VERSION 5.8 ;
BUSBITCHARS "[]" ;
DIVIDERCHAR "/" ;
UNITS
    DATABASE MICRONS 1000 ;
END UNITS

VIA ino_fetch_via1_2_1000_440_1_2_410_410
  VIARULE via1Array ;
  CUTSIZE 0.19 0.19 ;
  LAYERS Metal1 Via1 Metal2 ;
  CUTSPACING 0.22 0.22 ;
  ENCLOSURE 0.05 0.125 0.005 0.05 ;
  ROWCOL 1 2 ;
END ino_fetch_via1_2_1000_440_1_2_410_410

VIA ino_fetch_via2_3_1000_440_1_2_410_410
  VIARULE via2Array ;
  CUTSIZE 0.19 0.19 ;
  LAYERS Metal2 Via2 Metal3 ;
  CUTSPACING 0.22 0.22 ;
  ENCLOSURE 0.005 0.05 0.05 0.005 ;
  ROWCOL 1 2 ;
END ino_fetch_via2_3_1000_440_1_2_410_410

VIA ino_fetch_via3_4_1000_440_1_2_410_410
  VIARULE via3Array ;
  CUTSIZE 0.19 0.19 ;
  LAYERS Metal3 Via3 Metal4 ;
  CUTSPACING 0.22 0.22 ;
  ENCLOSURE 0.05 0.005 0.2 0.05 ;
  ROWCOL 1 2 ;
END ino_fetch_via3_4_1000_440_1_2_410_410

VIA ino_fetch_via1_2_1000_350_1_2_410_410
  VIARULE via1Array ;
  CUTSIZE 0.19 0.19 ;
  LAYERS Metal1 Via1 Metal2 ;
  CUTSPACING 0.22 0.22 ;
  ENCLOSURE 0.05 0.08 0.005 0.05 ;
  ROWCOL 1 2 ;
END ino_fetch_via1_2_1000_350_1_2_410_410

VIA ino_fetch_via2_3_1000_530_1_2_410_410
  VIARULE via2Array ;
  CUTSIZE 0.19 0.19 ;
  LAYERS Metal2 Via2 Metal3 ;
  CUTSPACING 0.22 0.22 ;
  ENCLOSURE 0.005 0.05 0.05 0.005 ;
  ROWCOL 1 2 ;
END ino_fetch_via2_3_1000_530_1_2_410_410

VIA ino_fetch_via3_4_1000_350_1_2_410_410
  VIARULE via3Array ;
  CUTSIZE 0.19 0.19 ;
  LAYERS Metal3 Via3 Metal4 ;
  CUTSPACING 0.22 0.22 ;
  ENCLOSURE 0.05 0.005 0.2 0.05 ;
  ROWCOL 1 2 ;
END ino_fetch_via3_4_1000_350_1_2_410_410

VIA ino_fetch_via4_5_1000_2000_1_1_840_840
  VIARULE viaTop1Array ;
  CUTSIZE 0.42 0.42 ;
  LAYERS Metal4 TopVia1 TopMetal1 ;
  CUTSPACING 0.42 0.42 ;
  ENCLOSURE 0.29 0.1 0.42 0.79 ;
END ino_fetch_via4_5_1000_2000_1_1_840_840

VIA ino_fetch_via4_5_1000_1640_1_1_840_840
  VIARULE viaTop1Array ;
  CUTSIZE 0.42 0.42 ;
  LAYERS Metal4 TopVia1 TopMetal1 ;
  CUTSPACING 0.42 0.42 ;
  ENCLOSURE 0.29 0.1 0.42 0.61 ;
END ino_fetch_via4_5_1000_1640_1_1_840_840

VIA ino_fetch_via4_5_4420_2000_1_4_840_840
  VIARULE viaTop1Array ;
  CUTSIZE 0.42 0.42 ;
  LAYERS Metal4 TopVia1 TopMetal1 ;
  CUTSPACING 0.42 0.42 ;
  ENCLOSURE 0.74 0.79 0.42 0.79 ;
  ROWCOL 1 4 ;
END ino_fetch_via4_5_4420_2000_1_4_840_840

VIA ino_fetch_via4_5_2810_2000_1_2_840_840
  VIARULE viaTop1Array ;
  CUTSIZE 0.42 0.42 ;
  LAYERS Metal4 TopVia1 TopMetal1 ;
  CUTSPACING 0.42 0.42 ;
  ENCLOSURE 0.775 0.79 0.42 0.79 ;
  ROWCOL 1 2 ;
END ino_fetch_via4_5_2810_2000_1_2_840_840

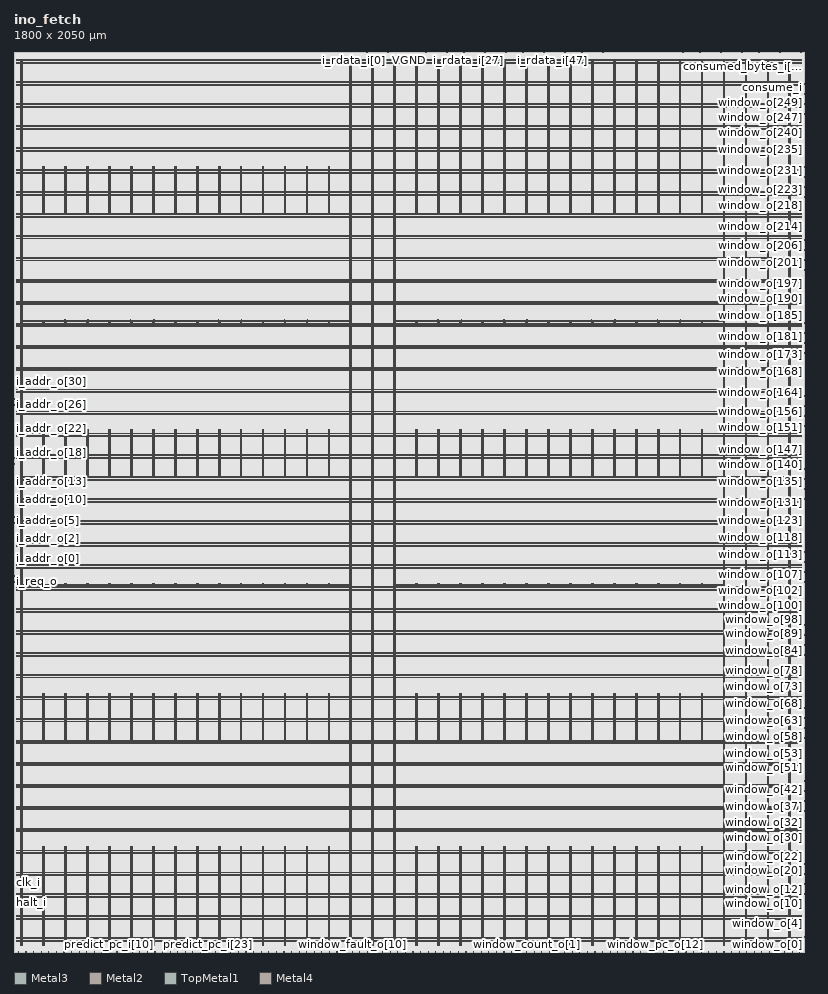
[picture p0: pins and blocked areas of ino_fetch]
MACRO ino_fetch
  FOREIGN ino_fetch 0 0 ;
  CLASS BLOCK ;
  SIZE 1800 BY 2050 ;
  PIN clk_i
    DIRECTION INPUT ;
    USE SIGNAL ;
    PORT
      LAYER Metal3 ;
        RECT  0 157.3 0.4 157.7 ;
    END
  END clk_i
  PIN consume_i
    DIRECTION INPUT ;
    USE SIGNAL ;
    PORT
      LAYER Metal3 ;
        RECT  1799.6 1969.18 1800 1969.58 ;
    END
  END consume_i
  PIN consumed_bytes_i[0]
    DIRECTION INPUT ;
    USE SIGNAL ;
    PORT
      LAYER Metal3 ;
        RECT  1799.6 1976.74 1800 1977.14 ;
    END
  END consumed_bytes_i[0]
  PIN consumed_bytes_i[1]
    DIRECTION INPUT ;
    USE SIGNAL ;
    PORT
      LAYER Metal3 ;
        RECT  1799.6 1984.3 1800 1984.7 ;
    END
  END consumed_bytes_i[1]
  PIN consumed_bytes_i[2]
    DIRECTION INPUT ;
    USE SIGNAL ;
    PORT
      LAYER Metal3 ;
        RECT  1799.6 1991.86 1800 1992.26 ;
    END
  END consumed_bytes_i[2]
  PIN consumed_bytes_i[3]
    DIRECTION INPUT ;
    USE SIGNAL ;
    PORT
      LAYER Metal3 ;
        RECT  1799.6 1999.42 1800 1999.82 ;
    END
  END consumed_bytes_i[3]
  PIN consumed_bytes_i[4]
    DIRECTION INPUT ;
    USE SIGNAL ;
    PORT
      LAYER Metal3 ;
        RECT  1799.6 2006.98 1800 2007.38 ;
    END
  END consumed_bytes_i[4]
  PIN consumed_bytes_i[5]
    DIRECTION INPUT ;
    USE SIGNAL ;
    PORT
      LAYER Metal3 ;
        RECT  1799.6 2014.54 1800 2014.94 ;
    END
  END consumed_bytes_i[5]
  PIN decode_stop_i
    DIRECTION INPUT ;
    USE SIGNAL ;
    PORT
      LAYER Metal2 ;
        RECT  9.88 0 10.28 0.4 ;
    END
  END decode_stop_i
  PIN halt_i
    DIRECTION INPUT ;
    USE SIGNAL ;
    PORT
      LAYER Metal3 ;
        RECT  0 130.42 0.4 130.82 ;
    END
  END halt_i
  PIN i_addr_o[0]
    DIRECTION OUTPUT ;
    USE SIGNAL ;
    PORT
      LAYER Metal3 ;
        RECT  0 896.5 0.4 896.9 ;
    END
  END i_addr_o[0]
  PIN i_addr_o[10]
    DIRECTION OUTPUT ;
    USE SIGNAL ;
    PORT
      LAYER Metal3 ;
        RECT  0 1030.9 0.4 1031.3 ;
    END
  END i_addr_o[10]
  PIN i_addr_o[11]
    DIRECTION OUTPUT ;
    USE SIGNAL ;
    PORT
      LAYER Metal3 ;
        RECT  0 1044.34 0.4 1044.74 ;
    END
  END i_addr_o[11]
  PIN i_addr_o[12]
    DIRECTION OUTPUT ;
    USE SIGNAL ;
    PORT
      LAYER Metal3 ;
        RECT  0 1057.78 0.4 1058.18 ;
    END
  END i_addr_o[12]
  PIN i_addr_o[13]
    DIRECTION OUTPUT ;
    USE SIGNAL ;
    PORT
      LAYER Metal3 ;
        RECT  0 1071.22 0.4 1071.62 ;
    END
  END i_addr_o[13]
  PIN i_addr_o[14]
    DIRECTION OUTPUT ;
    USE SIGNAL ;
    PORT
      LAYER Metal3 ;
        RECT  0 1084.66 0.4 1085.06 ;
    END
  END i_addr_o[14]
  PIN i_addr_o[15]
    DIRECTION OUTPUT ;
    USE SIGNAL ;
    PORT
      LAYER Metal3 ;
        RECT  0 1098.1 0.4 1098.5 ;
    END
  END i_addr_o[15]
  PIN i_addr_o[16]
    DIRECTION OUTPUT ;
    USE SIGNAL ;
    PORT
      LAYER Metal3 ;
        RECT  0 1111.54 0.4 1111.94 ;
    END
  END i_addr_o[16]
  PIN i_addr_o[17]
    DIRECTION OUTPUT ;
    USE SIGNAL ;
    PORT
      LAYER Metal3 ;
        RECT  0 1124.98 0.4 1125.38 ;
    END
  END i_addr_o[17]
  PIN i_addr_o[18]
    DIRECTION OUTPUT ;
    USE SIGNAL ;
    PORT
      LAYER Metal3 ;
        RECT  0 1138.42 0.4 1138.82 ;
    END
  END i_addr_o[18]
  PIN i_addr_o[19]
    DIRECTION OUTPUT ;
    USE SIGNAL ;
    PORT
      LAYER Metal3 ;
        RECT  0 1151.86 0.4 1152.26 ;
    END
  END i_addr_o[19]
  PIN i_addr_o[1]
    DIRECTION OUTPUT ;
    USE SIGNAL ;
    PORT
      LAYER Metal3 ;
        RECT  0 909.94 0.4 910.34 ;
    END
  END i_addr_o[1]
  PIN i_addr_o[20]
    DIRECTION OUTPUT ;
    USE SIGNAL ;
    PORT
      LAYER Metal3 ;
        RECT  0 1165.3 0.4 1165.7 ;
    END
  END i_addr_o[20]
  PIN i_addr_o[21]
    DIRECTION OUTPUT ;
    USE SIGNAL ;
    PORT
      LAYER Metal3 ;
        RECT  0 1178.74 0.4 1179.14 ;
    END
  END i_addr_o[21]
  PIN i_addr_o[22]
    DIRECTION OUTPUT ;
    USE SIGNAL ;
    PORT
      LAYER Metal3 ;
        RECT  0 1192.18 0.4 1192.58 ;
    END
  END i_addr_o[22]
  PIN i_addr_o[23]
    DIRECTION OUTPUT ;
    USE SIGNAL ;
    PORT
      LAYER Metal3 ;
        RECT  0 1205.62 0.4 1206.02 ;
    END
  END i_addr_o[23]
  PIN i_addr_o[24]
    DIRECTION OUTPUT ;
    USE SIGNAL ;
    PORT
      LAYER Metal3 ;
        RECT  0 1219.06 0.4 1219.46 ;
    END
  END i_addr_o[24]
  PIN i_addr_o[25]
    DIRECTION OUTPUT ;
    USE SIGNAL ;
    PORT
      LAYER Metal3 ;
        RECT  0 1232.5 0.4 1232.9 ;
    END
  END i_addr_o[25]
  PIN i_addr_o[26]
    DIRECTION OUTPUT ;
    USE SIGNAL ;
    PORT
      LAYER Metal3 ;
        RECT  0 1245.94 0.4 1246.34 ;
    END
  END i_addr_o[26]
  PIN i_addr_o[27]
    DIRECTION OUTPUT ;
    USE SIGNAL ;
    PORT
      LAYER Metal3 ;
        RECT  0 1259.38 0.4 1259.78 ;
    END
  END i_addr_o[27]
  PIN i_addr_o[28]
    DIRECTION OUTPUT ;
    USE SIGNAL ;
    PORT
      LAYER Metal3 ;
        RECT  0 1272.82 0.4 1273.22 ;
    END
  END i_addr_o[28]
  PIN i_addr_o[29]
    DIRECTION OUTPUT ;
    USE SIGNAL ;
    PORT
      LAYER Metal3 ;
        RECT  0 1286.26 0.4 1286.66 ;
    END
  END i_addr_o[29]
  PIN i_addr_o[2]
    DIRECTION OUTPUT ;
    USE SIGNAL ;
    PORT
      LAYER Metal3 ;
        RECT  0 923.38 0.4 923.78 ;
    END
  END i_addr_o[2]
  PIN i_addr_o[30]
    DIRECTION OUTPUT ;
    USE SIGNAL ;
    PORT
      LAYER Metal3 ;
        RECT  0 1299.7 0.4 1300.1 ;
    END
  END i_addr_o[30]
  PIN i_addr_o[31]
    DIRECTION OUTPUT ;
    USE SIGNAL ;
    PORT
      LAYER Metal3 ;
        RECT  0 1313.14 0.4 1313.54 ;
    END
  END i_addr_o[31]
  PIN i_addr_o[3]
    DIRECTION OUTPUT ;
    USE SIGNAL ;
    PORT
      LAYER Metal3 ;
        RECT  0 936.82 0.4 937.22 ;
    END
  END i_addr_o[3]
  PIN i_addr_o[4]
    DIRECTION OUTPUT ;
    USE SIGNAL ;
    PORT
      LAYER Metal3 ;
        RECT  0 950.26 0.4 950.66 ;
    END
  END i_addr_o[4]
  PIN i_addr_o[5]
    DIRECTION OUTPUT ;
    USE SIGNAL ;
    PORT
      LAYER Metal3 ;
        RECT  0 963.7 0.4 964.1 ;
    END
  END i_addr_o[5]
  PIN i_addr_o[6]
    DIRECTION OUTPUT ;
    USE SIGNAL ;
    PORT
      LAYER Metal3 ;
        RECT  0 977.14 0.4 977.54 ;
    END
  END i_addr_o[6]
  PIN i_addr_o[7]
    DIRECTION OUTPUT ;
    USE SIGNAL ;
    PORT
      LAYER Metal3 ;
        RECT  0 990.58 0.4 990.98 ;
    END
  END i_addr_o[7]
  PIN i_addr_o[8]
    DIRECTION OUTPUT ;
    USE SIGNAL ;
    PORT
      LAYER Metal3 ;
        RECT  0 1004.02 0.4 1004.42 ;
    END
  END i_addr_o[8]
  PIN i_addr_o[9]
    DIRECTION OUTPUT ;
    USE SIGNAL ;
    PORT
      LAYER Metal3 ;
        RECT  0 1017.46 0.4 1017.86 ;
    END
  END i_addr_o[9]
  PIN i_fault_i
    DIRECTION INPUT ;
    USE SIGNAL ;
    PORT
      LAYER Metal3 ;
        RECT  0 883.06 0.4 883.46 ;
    END
  END i_fault_i
  PIN i_rdata_i[0]
    DIRECTION INPUT ;
    USE SIGNAL ;
    PORT
      LAYER Metal2 ;
        RECT  775 2049.6 775.4 2050 ;
    END
  END i_rdata_i[0]
  PIN i_rdata_i[10]
    DIRECTION INPUT ;
    USE SIGNAL ;
    PORT
      LAYER Metal2 ;
        RECT  871 2049.6 871.4 2050 ;
    END
  END i_rdata_i[10]
  PIN i_rdata_i[11]
    DIRECTION INPUT ;
    USE SIGNAL ;
    PORT
      LAYER Metal2 ;
        RECT  880.6 2049.6 881 2050 ;
    END
  END i_rdata_i[11]
  PIN i_rdata_i[12]
    DIRECTION INPUT ;
    USE SIGNAL ;
    PORT
      LAYER Metal2 ;
        RECT  890.2 2049.6 890.6 2050 ;
    END
  END i_rdata_i[12]
  PIN i_rdata_i[13]
    DIRECTION INPUT ;
    USE SIGNAL ;
    PORT
      LAYER Metal2 ;
        RECT  899.8 2049.6 900.2 2050 ;
    END
  END i_rdata_i[13]
  PIN i_rdata_i[14]
    DIRECTION INPUT ;
    USE SIGNAL ;
    PORT
      LAYER Metal2 ;
        RECT  909.4 2049.6 909.8 2050 ;
    END
  END i_rdata_i[14]
  PIN i_rdata_i[15]
    DIRECTION INPUT ;
    USE SIGNAL ;
    PORT
      LAYER Metal2 ;
        RECT  919 2049.6 919.4 2050 ;
    END
  END i_rdata_i[15]
  PIN i_rdata_i[16]
    DIRECTION INPUT ;
    USE SIGNAL ;
    PORT
      LAYER Metal2 ;
        RECT  928.6 2049.6 929 2050 ;
    END
  END i_rdata_i[16]
  PIN i_rdata_i[17]
    DIRECTION INPUT ;
    USE SIGNAL ;
    PORT
      LAYER Metal2 ;
        RECT  938.2 2049.6 938.6 2050 ;
    END
  END i_rdata_i[17]
  PIN i_rdata_i[18]
    DIRECTION INPUT ;
    USE SIGNAL ;
    PORT
      LAYER Metal2 ;
        RECT  947.8 2049.6 948.2 2050 ;
    END
  END i_rdata_i[18]
  PIN i_rdata_i[19]
    DIRECTION INPUT ;
    USE SIGNAL ;
    PORT
      LAYER Metal2 ;
        RECT  957.4 2049.6 957.8 2050 ;
    END
  END i_rdata_i[19]
  PIN i_rdata_i[1]
    DIRECTION INPUT ;
    USE SIGNAL ;
    PORT
      LAYER Metal2 ;
        RECT  784.6 2049.6 785 2050 ;
    END
  END i_rdata_i[1]
  PIN i_rdata_i[20]
    DIRECTION INPUT ;
    USE SIGNAL ;
    PORT
      LAYER Metal2 ;
        RECT  967 2049.6 967.4 2050 ;
    END
  END i_rdata_i[20]
  PIN i_rdata_i[21]
    DIRECTION INPUT ;
    USE SIGNAL ;
    PORT
      LAYER Metal2 ;
        RECT  976.6 2049.6 977 2050 ;
    END
  END i_rdata_i[21]
  PIN i_rdata_i[22]
    DIRECTION INPUT ;
    USE SIGNAL ;
    PORT
      LAYER Metal2 ;
        RECT  986.2 2049.6 986.6 2050 ;
    END
  END i_rdata_i[22]
  PIN i_rdata_i[23]
    DIRECTION INPUT ;
    USE SIGNAL ;
    PORT
      LAYER Metal2 ;
        RECT  995.8 2049.6 996.2 2050 ;
    END
  END i_rdata_i[23]
  PIN i_rdata_i[24]
    DIRECTION INPUT ;
    USE SIGNAL ;
    PORT
      LAYER Metal2 ;
        RECT  1005.4 2049.6 1005.8 2050 ;
    END
  END i_rdata_i[24]
  PIN i_rdata_i[25]
    DIRECTION INPUT ;
    USE SIGNAL ;
    PORT
      LAYER Metal2 ;
        RECT  1015 2049.6 1015.4 2050 ;
    END
  END i_rdata_i[25]
  PIN i_rdata_i[26]
    DIRECTION INPUT ;
    USE SIGNAL ;
    PORT
      LAYER Metal2 ;
        RECT  1024.6 2049.6 1025 2050 ;
    END
  END i_rdata_i[26]
  PIN i_rdata_i[27]
    DIRECTION INPUT ;
    USE SIGNAL ;
    PORT
      LAYER Metal2 ;
        RECT  1034.2 2049.6 1034.6 2050 ;
    END
  END i_rdata_i[27]
  PIN i_rdata_i[28]
    DIRECTION INPUT ;
    USE SIGNAL ;
    PORT
      LAYER Metal2 ;
        RECT  1043.8 2049.6 1044.2 2050 ;
    END
  END i_rdata_i[28]
  PIN i_rdata_i[29]
    DIRECTION INPUT ;
    USE SIGNAL ;
    PORT
      LAYER Metal2 ;
        RECT  1053.4 2049.6 1053.8 2050 ;
    END
  END i_rdata_i[29]
  PIN i_rdata_i[2]
    DIRECTION INPUT ;
    USE SIGNAL ;
    PORT
      LAYER Metal2 ;
        RECT  794.2 2049.6 794.6 2050 ;
    END
  END i_rdata_i[2]
  PIN i_rdata_i[30]
    DIRECTION INPUT ;
    USE SIGNAL ;
    PORT
      LAYER Metal2 ;
        RECT  1063 2049.6 1063.4 2050 ;
    END
  END i_rdata_i[30]
  PIN i_rdata_i[31]
    DIRECTION INPUT ;
    USE SIGNAL ;
    PORT
      LAYER Metal2 ;
        RECT  1072.6 2049.6 1073 2050 ;
    END
  END i_rdata_i[31]
  PIN i_rdata_i[32]
    DIRECTION INPUT ;
    USE SIGNAL ;
    PORT
      LAYER Metal2 ;
        RECT  1082.2 2049.6 1082.6 2050 ;
    END
  END i_rdata_i[32]
  PIN i_rdata_i[33]
    DIRECTION INPUT ;
    USE SIGNAL ;
    PORT
      LAYER Metal2 ;
        RECT  1091.8 2049.6 1092.2 2050 ;
    END
  END i_rdata_i[33]
  PIN i_rdata_i[34]
    DIRECTION INPUT ;
    USE SIGNAL ;
    PORT
      LAYER Metal2 ;
        RECT  1101.4 2049.6 1101.8 2050 ;
    END
  END i_rdata_i[34]
  PIN i_rdata_i[35]
    DIRECTION INPUT ;
    USE SIGNAL ;
    PORT
      LAYER Metal2 ;
        RECT  1111 2049.6 1111.4 2050 ;
    END
  END i_rdata_i[35]
  PIN i_rdata_i[36]
    DIRECTION INPUT ;
    USE SIGNAL ;
    PORT
      LAYER Metal2 ;
        RECT  1120.6 2049.6 1121 2050 ;
    END
  END i_rdata_i[36]
  PIN i_rdata_i[37]
    DIRECTION INPUT ;
    USE SIGNAL ;
    PORT
      LAYER Metal2 ;
        RECT  1130.2 2049.6 1130.6 2050 ;
    END
  END i_rdata_i[37]
  PIN i_rdata_i[38]
    DIRECTION INPUT ;
    USE SIGNAL ;
    PORT
      LAYER Metal2 ;
        RECT  1139.8 2049.6 1140.2 2050 ;
    END
  END i_rdata_i[38]
  PIN i_rdata_i[39]
    DIRECTION INPUT ;
    USE SIGNAL ;
    PORT
      LAYER Metal2 ;
        RECT  1149.4 2049.6 1149.8 2050 ;
    END
  END i_rdata_i[39]
  PIN i_rdata_i[3]
    DIRECTION INPUT ;
    USE SIGNAL ;
    PORT
      LAYER Metal2 ;
        RECT  803.8 2049.6 804.2 2050 ;
    END
  END i_rdata_i[3]
  PIN i_rdata_i[40]
    DIRECTION INPUT ;
    USE SIGNAL ;
    PORT
      LAYER Metal2 ;
        RECT  1159 2049.6 1159.4 2050 ;
    END
  END i_rdata_i[40]
  PIN i_rdata_i[41]
    DIRECTION INPUT ;
    USE SIGNAL ;
    PORT
      LAYER Metal2 ;
        RECT  1168.6 2049.6 1169 2050 ;
    END
  END i_rdata_i[41]
  PIN i_rdata_i[42]
    DIRECTION INPUT ;
    USE SIGNAL ;
    PORT
      LAYER Metal2 ;
        RECT  1178.2 2049.6 1178.6 2050 ;
    END
  END i_rdata_i[42]
  PIN i_rdata_i[43]
    DIRECTION INPUT ;
    USE SIGNAL ;
    PORT
      LAYER Metal2 ;
        RECT  1187.8 2049.6 1188.2 2050 ;
    END
  END i_rdata_i[43]
  PIN i_rdata_i[44]
    DIRECTION INPUT ;
    USE SIGNAL ;
    PORT
      LAYER Metal2 ;
        RECT  1197.4 2049.6 1197.8 2050 ;
    END
  END i_rdata_i[44]
  PIN i_rdata_i[45]
    DIRECTION INPUT ;
    USE SIGNAL ;
    PORT
      LAYER Metal2 ;
        RECT  1207 2049.6 1207.4 2050 ;
    END
  END i_rdata_i[45]
  PIN i_rdata_i[46]
    DIRECTION INPUT ;
    USE SIGNAL ;
    PORT
      LAYER Metal2 ;
        RECT  1216.6 2049.6 1217 2050 ;
    END
  END i_rdata_i[46]
  PIN i_rdata_i[47]
    DIRECTION INPUT ;
    USE SIGNAL ;
    PORT
      LAYER Metal2 ;
        RECT  1226.2 2049.6 1226.6 2050 ;
    END
  END i_rdata_i[47]
  PIN i_rdata_i[48]
    DIRECTION INPUT ;
    USE SIGNAL ;
    PORT
      LAYER Metal2 ;
        RECT  1235.8 2049.6 1236.2 2050 ;
    END
  END i_rdata_i[48]
  PIN i_rdata_i[49]
    DIRECTION INPUT ;
    USE SIGNAL ;
    PORT
      LAYER Metal2 ;
        RECT  1245.4 2049.6 1245.8 2050 ;
    END
  END i_rdata_i[49]
  PIN i_rdata_i[4]
    DIRECTION INPUT ;
    USE SIGNAL ;
    PORT
      LAYER Metal2 ;
        RECT  813.4 2049.6 813.8 2050 ;
    END
  END i_rdata_i[4]
  PIN i_rdata_i[50]
    DIRECTION INPUT ;
    USE SIGNAL ;
    PORT
      LAYER Metal2 ;
        RECT  1255 2049.6 1255.4 2050 ;
    END
  END i_rdata_i[50]
  PIN i_rdata_i[51]
    DIRECTION INPUT ;
    USE SIGNAL ;
    PORT
      LAYER Metal2 ;
        RECT  1264.6 2049.6 1265 2050 ;
    END
  END i_rdata_i[51]
  PIN i_rdata_i[52]
    DIRECTION INPUT ;
    USE SIGNAL ;
    PORT
      LAYER Metal2 ;
        RECT  1274.2 2049.6 1274.6 2050 ;
    END
  END i_rdata_i[52]
  PIN i_rdata_i[53]
    DIRECTION INPUT ;
    USE SIGNAL ;
    PORT
      LAYER Metal2 ;
        RECT  1283.8 2049.6 1284.2 2050 ;
    END
  END i_rdata_i[53]
  PIN i_rdata_i[54]
    DIRECTION INPUT ;
    USE SIGNAL ;
    PORT
      LAYER Metal2 ;
        RECT  1293.4 2049.6 1293.8 2050 ;
    END
  END i_rdata_i[54]
  PIN i_rdata_i[55]
    DIRECTION INPUT ;
    USE SIGNAL ;
    PORT
      LAYER Metal2 ;
        RECT  1303 2049.6 1303.4 2050 ;
    END
  END i_rdata_i[55]
  PIN i_rdata_i[56]
    DIRECTION INPUT ;
    USE SIGNAL ;
    PORT
      LAYER Metal2 ;
        RECT  1312.6 2049.6 1313 2050 ;
    END
  END i_rdata_i[56]
  PIN i_rdata_i[57]
    DIRECTION INPUT ;
    USE SIGNAL ;
    PORT
      LAYER Metal2 ;
        RECT  1322.2 2049.6 1322.6 2050 ;
    END
  END i_rdata_i[57]
  PIN i_rdata_i[58]
    DIRECTION INPUT ;
    USE SIGNAL ;
    PORT
      LAYER Metal2 ;
        RECT  1331.8 2049.6 1332.2 2050 ;
    END
  END i_rdata_i[58]
  PIN i_rdata_i[59]
    DIRECTION INPUT ;
    USE SIGNAL ;
    PORT
      LAYER Metal2 ;
        RECT  1341.4 2049.6 1341.8 2050 ;
    END
  END i_rdata_i[59]
  PIN i_rdata_i[5]
    DIRECTION INPUT ;
    USE SIGNAL ;
    PORT
      LAYER Metal2 ;
        RECT  823 2049.6 823.4 2050 ;
    END
  END i_rdata_i[5]
  PIN i_rdata_i[60]
    DIRECTION INPUT ;
    USE SIGNAL ;
    PORT
      LAYER Metal2 ;
        RECT  1351 2049.6 1351.4 2050 ;
    END
  END i_rdata_i[60]
  PIN i_rdata_i[61]
    DIRECTION INPUT ;
    USE SIGNAL ;
    PORT
      LAYER Metal2 ;
        RECT  1360.6 2049.6 1361 2050 ;
    END
  END i_rdata_i[61]
  PIN i_rdata_i[62]
    DIRECTION INPUT ;
    USE SIGNAL ;
    PORT
      LAYER Metal2 ;
        RECT  1370.2 2049.6 1370.6 2050 ;
    END
  END i_rdata_i[62]
  PIN i_rdata_i[63]
    DIRECTION INPUT ;
    USE SIGNAL ;
    PORT
      LAYER Metal2 ;
        RECT  1379.8 2049.6 1380.2 2050 ;
    END
  END i_rdata_i[63]
  PIN i_rdata_i[6]
    DIRECTION INPUT ;
    USE SIGNAL ;
    PORT
      LAYER Metal2 ;
        RECT  832.6 2049.6 833 2050 ;
    END
  END i_rdata_i[6]
  PIN i_rdata_i[7]
    DIRECTION INPUT ;
    USE SIGNAL ;
    PORT
      LAYER Metal2 ;
        RECT  842.2 2049.6 842.6 2050 ;
    END
  END i_rdata_i[7]
  PIN i_rdata_i[8]
    DIRECTION INPUT ;
    USE SIGNAL ;
    PORT
      LAYER Metal2 ;
        RECT  851.8 2049.6 852.2 2050 ;
    END
  END i_rdata_i[8]
  PIN i_rdata_i[9]
    DIRECTION INPUT ;
    USE SIGNAL ;
    PORT
      LAYER Metal2 ;
        RECT  861.4 2049.6 861.8 2050 ;
    END
  END i_rdata_i[9]
  PIN i_ready_i
    DIRECTION INPUT ;
    USE SIGNAL ;
    PORT
      LAYER Metal3 ;
        RECT  0 856.18 0.4 856.58 ;
    END
  END i_ready_i
  PIN i_req_o
    DIRECTION OUTPUT ;
    USE SIGNAL ;
    PORT
      LAYER Metal3 ;
        RECT  0 842.74 0.4 843.14 ;
    END
  END i_req_o
  PIN i_rvalid_i
    DIRECTION INPUT ;
    USE SIGNAL ;
    PORT
      LAYER Metal3 ;
        RECT  0 869.62 0.4 870.02 ;
    END
  END i_rvalid_i
  PIN predict_pc_i[0]
    DIRECTION INPUT ;
    USE SIGNAL ;
    PORT
      LAYER Metal2 ;
        RECT  44.44 0 44.84 0.4 ;
    END
  END predict_pc_i[0]
  PIN predict_pc_i[10]
    DIRECTION INPUT ;
    USE SIGNAL ;
    PORT
      LAYER Metal2 ;
        RECT  217.24 0 217.64 0.4 ;
    END
  END predict_pc_i[10]
  PIN predict_pc_i[11]
    DIRECTION INPUT ;
    USE SIGNAL ;
    PORT
      LAYER Metal2 ;
        RECT  234.52 0 234.92 0.4 ;
    END
  END predict_pc_i[11]
  PIN predict_pc_i[12]
    DIRECTION INPUT ;
    USE SIGNAL ;
    PORT
      LAYER Metal2 ;
        RECT  251.8 0 252.2 0.4 ;
    END
  END predict_pc_i[12]
  PIN predict_pc_i[13]
    DIRECTION INPUT ;
    USE SIGNAL ;
    PORT
      LAYER Metal2 ;
        RECT  269.08 0 269.48 0.4 ;
    END
  END predict_pc_i[13]
  PIN predict_pc_i[14]
    DIRECTION INPUT ;
    USE SIGNAL ;
    PORT
      LAYER Metal2 ;
        RECT  286.36 0 286.76 0.4 ;
    END
  END predict_pc_i[14]
  PIN predict_pc_i[15]
    DIRECTION INPUT ;
    USE SIGNAL ;
    PORT
      LAYER Metal2 ;
        RECT  303.64 0 304.04 0.4 ;
    END
  END predict_pc_i[15]
  PIN predict_pc_i[16]
    DIRECTION INPUT ;
    USE SIGNAL ;
    PORT
      LAYER Metal2 ;
        RECT  320.92 0 321.32 0.4 ;
    END
  END predict_pc_i[16]
  PIN predict_pc_i[17]
    DIRECTION INPUT ;
    USE SIGNAL ;
    PORT
      LAYER Metal2 ;
        RECT  338.2 0 338.6 0.4 ;
    END
  END predict_pc_i[17]
  PIN predict_pc_i[18]
    DIRECTION INPUT ;
    USE SIGNAL ;
    PORT
      LAYER Metal2 ;
        RECT  355.48 0 355.88 0.4 ;
    END
  END predict_pc_i[18]
  PIN predict_pc_i[19]
    DIRECTION INPUT ;
    USE SIGNAL ;
    PORT
      LAYER Metal2 ;
        RECT  372.76 0 373.16 0.4 ;
    END
  END predict_pc_i[19]
  PIN predict_pc_i[1]
    DIRECTION INPUT ;
    USE SIGNAL ;
    PORT
      LAYER Metal2 ;
        RECT  61.72 0 62.12 0.4 ;
    END
  END predict_pc_i[1]
  PIN predict_pc_i[20]
    DIRECTION INPUT ;
    USE SIGNAL ;
    PORT
      LAYER Metal2 ;
        RECT  390.04 0 390.44 0.4 ;
    END
  END predict_pc_i[20]
  PIN predict_pc_i[21]
    DIRECTION INPUT ;
    USE SIGNAL ;
    PORT
      LAYER Metal2 ;
        RECT  407.32 0 407.72 0.4 ;
    END
  END predict_pc_i[21]
  PIN predict_pc_i[22]
    DIRECTION INPUT ;
    USE SIGNAL ;
    PORT
      LAYER Metal2 ;
        RECT  424.6 0 425 0.4 ;
    END
  END predict_pc_i[22]
  PIN predict_pc_i[23]
    DIRECTION INPUT ;
    USE SIGNAL ;
    PORT
      LAYER Metal2 ;
        RECT  441.88 0 442.28 0.4 ;
    END
  END predict_pc_i[23]
  PIN predict_pc_i[24]
    DIRECTION INPUT ;
    USE SIGNAL ;
    PORT
      LAYER Metal2 ;
        RECT  459.16 0 459.56 0.4 ;
    END
  END predict_pc_i[24]
  PIN predict_pc_i[25]
    DIRECTION INPUT ;
    USE SIGNAL ;
    PORT
      LAYER Metal2 ;
        RECT  476.44 0 476.84 0.4 ;
    END
  END predict_pc_i[25]
  PIN predict_pc_i[26]
    DIRECTION INPUT ;
    USE SIGNAL ;
    PORT
      LAYER Metal2 ;
        RECT  493.72 0 494.12 0.4 ;
    END
  END predict_pc_i[26]
  PIN predict_pc_i[27]
    DIRECTION INPUT ;
    USE SIGNAL ;
    PORT
      LAYER Metal2 ;
        RECT  511 0 511.4 0.4 ;
    END
  END predict_pc_i[27]
  PIN predict_pc_i[28]
    DIRECTION INPUT ;
    USE SIGNAL ;
    PORT
      LAYER Metal2 ;
        RECT  528.28 0 528.68 0.4 ;
    END
  END predict_pc_i[28]
  PIN predict_pc_i[29]
    DIRECTION INPUT ;
    USE SIGNAL ;
    PORT
      LAYER Metal2 ;
        RECT  545.56 0 545.96 0.4 ;
    END
  END predict_pc_i[29]
  PIN predict_pc_i[2]
    DIRECTION INPUT ;
    USE SIGNAL ;
    PORT
      LAYER Metal2 ;
        RECT  79 0 79.4 0.4 ;
    END
  END predict_pc_i[2]
  PIN predict_pc_i[30]
    DIRECTION INPUT ;
    USE SIGNAL ;
    PORT
      LAYER Metal2 ;
        RECT  562.84 0 563.24 0.4 ;
    END
  END predict_pc_i[30]
  PIN predict_pc_i[31]
    DIRECTION INPUT ;
    USE SIGNAL ;
    PORT
      LAYER Metal2 ;
        RECT  580.12 0 580.52 0.4 ;
    END
  END predict_pc_i[31]
  PIN predict_pc_i[3]
    DIRECTION INPUT ;
    USE SIGNAL ;
    PORT
      LAYER Metal2 ;
        RECT  96.28 0 96.68 0.4 ;
    END
  END predict_pc_i[3]
  PIN predict_pc_i[4]
    DIRECTION INPUT ;
    USE SIGNAL ;
    PORT
      LAYER Metal2 ;
        RECT  113.56 0 113.96 0.4 ;
    END
  END predict_pc_i[4]
  PIN predict_pc_i[5]
    DIRECTION INPUT ;
    USE SIGNAL ;
    PORT
      LAYER Metal2 ;
        RECT  130.84 0 131.24 0.4 ;
    END
  END predict_pc_i[5]
  PIN predict_pc_i[6]
    DIRECTION INPUT ;
    USE SIGNAL ;
    PORT
      LAYER Metal2 ;
        RECT  148.12 0 148.52 0.4 ;
    END
  END predict_pc_i[6]
  PIN predict_pc_i[7]
    DIRECTION INPUT ;
    USE SIGNAL ;
    PORT
      LAYER Metal2 ;
        RECT  165.4 0 165.8 0.4 ;
    END
  END predict_pc_i[7]
  PIN predict_pc_i[8]
    DIRECTION INPUT ;
    USE SIGNAL ;
    PORT
      LAYER Metal2 ;
        RECT  182.68 0 183.08 0.4 ;
    END
  END predict_pc_i[8]
  PIN predict_pc_i[9]
    DIRECTION INPUT ;
    USE SIGNAL ;
    PORT
      LAYER Metal2 ;
        RECT  199.96 0 200.36 0.4 ;
    END
  END predict_pc_i[9]
  PIN predict_valid_i
    DIRECTION INPUT ;
    USE SIGNAL ;
    PORT
      LAYER Metal2 ;
        RECT  27.16 0 27.56 0.4 ;
    END
  END predict_valid_i
  PIN recovery_pc_i[0]
    DIRECTION INPUT ;
    USE SIGNAL ;
    PORT
      LAYER Metal2 ;
        RECT  1495 2049.6 1495.4 2050 ;
    END
  END recovery_pc_i[0]
  PIN recovery_pc_i[10]
    DIRECTION INPUT ;
    USE SIGNAL ;
    PORT
      LAYER Metal2 ;
        RECT  1591 2049.6 1591.4 2050 ;
    END
  END recovery_pc_i[10]
  PIN recovery_pc_i[11]
    DIRECTION INPUT ;
    USE SIGNAL ;
    PORT
      LAYER Metal2 ;
        RECT  1600.6 2049.6 1601 2050 ;
    END
  END recovery_pc_i[11]
  PIN recovery_pc_i[12]
    DIRECTION INPUT ;
    USE SIGNAL ;
    PORT
      LAYER Metal2 ;
        RECT  1610.2 2049.6 1610.6 2050 ;
    END
  END recovery_pc_i[12]
  PIN recovery_pc_i[13]
    DIRECTION INPUT ;
    USE SIGNAL ;
    PORT
      LAYER Metal2 ;
        RECT  1619.8 2049.6 1620.2 2050 ;
    END
  END recovery_pc_i[13]
  PIN recovery_pc_i[14]
    DIRECTION INPUT ;
    USE SIGNAL ;
    PORT
      LAYER Metal2 ;
        RECT  1629.4 2049.6 1629.8 2050 ;
    END
  END recovery_pc_i[14]
  PIN recovery_pc_i[15]
    DIRECTION INPUT ;
    USE SIGNAL ;
    PORT
      LAYER Metal2 ;
        RECT  1639 2049.6 1639.4 2050 ;
    END
  END recovery_pc_i[15]
  PIN recovery_pc_i[16]
    DIRECTION INPUT ;
    USE SIGNAL ;
    PORT
      LAYER Metal2 ;
        RECT  1648.6 2049.6 1649 2050 ;
    END
  END recovery_pc_i[16]
  PIN recovery_pc_i[17]
    DIRECTION INPUT ;
    USE SIGNAL ;
    PORT
      LAYER Metal2 ;
        RECT  1658.2 2049.6 1658.6 2050 ;
    END
  END recovery_pc_i[17]
  PIN recovery_pc_i[18]
    DIRECTION INPUT ;
    USE SIGNAL ;
    PORT
      LAYER Metal2 ;
        RECT  1667.8 2049.6 1668.2 2050 ;
    END
  END recovery_pc_i[18]
  PIN recovery_pc_i[19]
    DIRECTION INPUT ;
    USE SIGNAL ;
    PORT
      LAYER Metal2 ;
        RECT  1677.4 2049.6 1677.8 2050 ;
    END
  END recovery_pc_i[19]
  PIN recovery_pc_i[1]
    DIRECTION INPUT ;
    USE SIGNAL ;
    PORT
      LAYER Metal2 ;
        RECT  1504.6 2049.6 1505 2050 ;
    END
  END recovery_pc_i[1]
  PIN recovery_pc_i[20]
    DIRECTION INPUT ;
    USE SIGNAL ;
    PORT
      LAYER Metal2 ;
        RECT  1687 2049.6 1687.4 2050 ;
    END
  END recovery_pc_i[20]
  PIN recovery_pc_i[21]
    DIRECTION INPUT ;
    USE SIGNAL ;
    PORT
      LAYER Metal2 ;
        RECT  1696.6 2049.6 1697 2050 ;
    END
  END recovery_pc_i[21]
  PIN recovery_pc_i[22]
    DIRECTION INPUT ;
    USE SIGNAL ;
    PORT
      LAYER Metal2 ;
        RECT  1706.2 2049.6 1706.6 2050 ;
    END
  END recovery_pc_i[22]
  PIN recovery_pc_i[23]
    DIRECTION INPUT ;
    USE SIGNAL ;
    PORT
      LAYER Metal2 ;
        RECT  1715.8 2049.6 1716.2 2050 ;
    END
  END recovery_pc_i[23]
  PIN recovery_pc_i[24]
    DIRECTION INPUT ;
    USE SIGNAL ;
    PORT
      LAYER Metal2 ;
        RECT  1725.4 2049.6 1725.8 2050 ;
    END
  END recovery_pc_i[24]
  PIN recovery_pc_i[25]
    DIRECTION INPUT ;
    USE SIGNAL ;
    PORT
      LAYER Metal2 ;
        RECT  1735 2049.6 1735.4 2050 ;
    END
  END recovery_pc_i[25]
  PIN recovery_pc_i[26]
    DIRECTION INPUT ;
    USE SIGNAL ;
    PORT
      LAYER Metal2 ;
        RECT  1744.6 2049.6 1745 2050 ;
    END
  END recovery_pc_i[26]
  PIN recovery_pc_i[27]
    DIRECTION INPUT ;
    USE SIGNAL ;
    PORT
      LAYER Metal2 ;
        RECT  1754.2 2049.6 1754.6 2050 ;
    END
  END recovery_pc_i[27]
  PIN recovery_pc_i[28]
    DIRECTION INPUT ;
    USE SIGNAL ;
    PORT
      LAYER Metal2 ;
        RECT  1763.8 2049.6 1764.2 2050 ;
    END
  END recovery_pc_i[28]
  PIN recovery_pc_i[29]
    DIRECTION INPUT ;
    USE SIGNAL ;
    PORT
      LAYER Metal2 ;
        RECT  1773.4 2049.6 1773.8 2050 ;
    END
  END recovery_pc_i[29]
  PIN recovery_pc_i[2]
    DIRECTION INPUT ;
    USE SIGNAL ;
    PORT
      LAYER Metal2 ;
        RECT  1514.2 2049.6 1514.6 2050 ;
    END
  END recovery_pc_i[2]
  PIN recovery_pc_i[30]
    DIRECTION INPUT ;
    USE SIGNAL ;
    PORT
      LAYER Metal2 ;
        RECT  1783 2049.6 1783.4 2050 ;
    END
  END recovery_pc_i[30]
  PIN recovery_pc_i[31]
    DIRECTION INPUT ;
    USE SIGNAL ;
    PORT
      LAYER Metal2 ;
        RECT  1792.6 2049.6 1793 2050 ;
    END
  END recovery_pc_i[31]
  PIN recovery_pc_i[3]
    DIRECTION INPUT ;
    USE SIGNAL ;
    PORT
      LAYER Metal2 ;
        RECT  1523.8 2049.6 1524.2 2050 ;
    END
  END recovery_pc_i[3]
  PIN recovery_pc_i[4]
    DIRECTION INPUT ;
    USE SIGNAL ;
    PORT
      LAYER Metal2 ;
        RECT  1533.4 2049.6 1533.8 2050 ;
    END
  END recovery_pc_i[4]
  PIN recovery_pc_i[5]
    DIRECTION INPUT ;
    USE SIGNAL ;
    PORT
      LAYER Metal2 ;
        RECT  1543 2049.6 1543.4 2050 ;
    END
  END recovery_pc_i[5]
  PIN recovery_pc_i[6]
    DIRECTION INPUT ;
    USE SIGNAL ;
    PORT
      LAYER Metal2 ;
        RECT  1552.6 2049.6 1553 2050 ;
    END
  END recovery_pc_i[6]
  PIN recovery_pc_i[7]
    DIRECTION INPUT ;
    USE SIGNAL ;
    PORT
      LAYER Metal2 ;
        RECT  1562.2 2049.6 1562.6 2050 ;
    END
  END recovery_pc_i[7]
  PIN recovery_pc_i[8]
    DIRECTION INPUT ;
    USE SIGNAL ;
    PORT
      LAYER Metal2 ;
        RECT  1571.8 2049.6 1572.2 2050 ;
    END
  END recovery_pc_i[8]
  PIN recovery_pc_i[9]
    DIRECTION INPUT ;
    USE SIGNAL ;
    PORT
      LAYER Metal2 ;
        RECT  1581.4 2049.6 1581.8 2050 ;
    END
  END recovery_pc_i[9]
  PIN recovery_valid_i
    DIRECTION INPUT ;
    USE SIGNAL ;
    PORT
      LAYER Metal2 ;
        RECT  1485.4 2049.6 1485.8 2050 ;
    END
  END recovery_valid_i
  PIN reset_i
    DIRECTION INPUT ;
    USE SIGNAL ;
    PORT
      LAYER Metal3 ;
        RECT  0 143.86 0.4 144.26 ;
    END
  END reset_i
  PIN window_count_o[0]
    DIRECTION OUTPUT ;
    USE SIGNAL ;
    PORT
      LAYER Metal2 ;
        RECT  1150.36 0 1150.76 0.4 ;
    END
  END window_count_o[0]
  PIN window_count_o[1]
    DIRECTION OUTPUT ;
    USE SIGNAL ;
    PORT
      LAYER Metal2 ;
        RECT  1167.64 0 1168.04 0.4 ;
    END
  END window_count_o[1]
  PIN window_count_o[2]
    DIRECTION OUTPUT ;
    USE SIGNAL ;
    PORT
      LAYER Metal2 ;
        RECT  1184.92 0 1185.32 0.4 ;
    END
  END window_count_o[2]
  PIN window_count_o[3]
    DIRECTION OUTPUT ;
    USE SIGNAL ;
    PORT
      LAYER Metal2 ;
        RECT  1202.2 0 1202.6 0.4 ;
    END
  END window_count_o[3]
  PIN window_count_o[4]
    DIRECTION OUTPUT ;
    USE SIGNAL ;
    PORT
      LAYER Metal2 ;
        RECT  1219.48 0 1219.88 0.4 ;
    END
  END window_count_o[4]
  PIN window_count_o[5]
    DIRECTION OUTPUT ;
    USE SIGNAL ;
    PORT
      LAYER Metal2 ;
        RECT  1236.76 0 1237.16 0.4 ;
    END
  END window_count_o[5]
  PIN window_fault_o[0]
    DIRECTION OUTPUT ;
    USE SIGNAL ;
    PORT
      LAYER Metal2 ;
        RECT  597.4 0 597.8 0.4 ;
    END
  END window_fault_o[0]
  PIN window_fault_o[10]
    DIRECTION OUTPUT ;
    USE SIGNAL ;
    PORT
      LAYER Metal2 ;
        RECT  770.2 0 770.6 0.4 ;
    END
  END window_fault_o[10]
  PIN window_fault_o[11]
    DIRECTION OUTPUT ;
    USE SIGNAL ;
    PORT
      LAYER Metal2 ;
        RECT  787.48 0 787.88 0.4 ;
    END
  END window_fault_o[11]
  PIN window_fault_o[12]
    DIRECTION OUTPUT ;
    USE SIGNAL ;
    PORT
      LAYER Metal2 ;
        RECT  804.76 0 805.16 0.4 ;
    END
  END window_fault_o[12]
  PIN window_fault_o[13]
    DIRECTION OUTPUT ;
    USE SIGNAL ;
    PORT
      LAYER Metal2 ;
        RECT  822.04 0 822.44 0.4 ;
    END
  END window_fault_o[13]
  PIN window_fault_o[14]
    DIRECTION OUTPUT ;
    USE SIGNAL ;
    PORT
      LAYER Metal2 ;
        RECT  839.32 0 839.72 0.4 ;
    END
  END window_fault_o[14]
  PIN window_fault_o[15]
    DIRECTION OUTPUT ;
    USE SIGNAL ;
    PORT
      LAYER Metal2 ;
        RECT  856.6 0 857 0.4 ;
    END
  END window_fault_o[15]
  PIN window_fault_o[16]
    DIRECTION OUTPUT ;
    USE SIGNAL ;
    PORT
      LAYER Metal2 ;
        RECT  873.88 0 874.28 0.4 ;
    END
  END window_fault_o[16]
  PIN window_fault_o[17]
    DIRECTION OUTPUT ;
    USE SIGNAL ;
    PORT
      LAYER Metal2 ;
        RECT  891.16 0 891.56 0.4 ;
    END
  END window_fault_o[17]
  PIN window_fault_o[18]
    DIRECTION OUTPUT ;
    USE SIGNAL ;
    PORT
      LAYER Metal2 ;
        RECT  908.44 0 908.84 0.4 ;
    END
  END window_fault_o[18]
  PIN window_fault_o[19]
    DIRECTION OUTPUT ;
    USE SIGNAL ;
    PORT
      LAYER Metal2 ;
        RECT  925.72 0 926.12 0.4 ;
    END
  END window_fault_o[19]
  PIN window_fault_o[1]
    DIRECTION OUTPUT ;
    USE SIGNAL ;
    PORT
      LAYER Metal2 ;
        RECT  614.68 0 615.08 0.4 ;
    END
  END window_fault_o[1]
  PIN window_fault_o[20]
    DIRECTION OUTPUT ;
    USE SIGNAL ;
    PORT
      LAYER Metal2 ;
        RECT  943 0 943.4 0.4 ;
    END
  END window_fault_o[20]
  PIN window_fault_o[21]
    DIRECTION OUTPUT ;
    USE SIGNAL ;
    PORT
      LAYER Metal2 ;
        RECT  960.28 0 960.68 0.4 ;
    END
  END window_fault_o[21]
  PIN window_fault_o[22]
    DIRECTION OUTPUT ;
    USE SIGNAL ;
    PORT
      LAYER Metal2 ;
        RECT  977.56 0 977.96 0.4 ;
    END
  END window_fault_o[22]
  PIN window_fault_o[23]
    DIRECTION OUTPUT ;
    USE SIGNAL ;
    PORT
      LAYER Metal2 ;
        RECT  994.84 0 995.24 0.4 ;
    END
  END window_fault_o[23]
  PIN window_fault_o[24]
    DIRECTION OUTPUT ;
    USE SIGNAL ;
    PORT
      LAYER Metal2 ;
        RECT  1012.12 0 1012.52 0.4 ;
    END
  END window_fault_o[24]
  PIN window_fault_o[25]
    DIRECTION OUTPUT ;
    USE SIGNAL ;
    PORT
      LAYER Metal2 ;
        RECT  1029.4 0 1029.8 0.4 ;
    END
  END window_fault_o[25]
  PIN window_fault_o[26]
    DIRECTION OUTPUT ;
    USE SIGNAL ;
    PORT
      LAYER Metal2 ;
        RECT  1046.68 0 1047.08 0.4 ;
    END
  END window_fault_o[26]
  PIN window_fault_o[27]
    DIRECTION OUTPUT ;
    USE SIGNAL ;
    PORT
      LAYER Metal2 ;
        RECT  1063.96 0 1064.36 0.4 ;
    END
  END window_fault_o[27]
  PIN window_fault_o[28]
    DIRECTION OUTPUT ;
    USE SIGNAL ;
    PORT
      LAYER Metal2 ;
        RECT  1081.24 0 1081.64 0.4 ;
    END
  END window_fault_o[28]
  PIN window_fault_o[29]
    DIRECTION OUTPUT ;
    USE SIGNAL ;
    PORT
      LAYER Metal2 ;
        RECT  1098.52 0 1098.92 0.4 ;
    END
  END window_fault_o[29]
  PIN window_fault_o[2]
    DIRECTION OUTPUT ;
    USE SIGNAL ;
    PORT
      LAYER Metal2 ;
        RECT  631.96 0 632.36 0.4 ;
    END
  END window_fault_o[2]
  PIN window_fault_o[30]
    DIRECTION OUTPUT ;
    USE SIGNAL ;
    PORT
      LAYER Metal2 ;
        RECT  1115.8 0 1116.2 0.4 ;
    END
  END window_fault_o[30]
  PIN window_fault_o[31]
    DIRECTION OUTPUT ;
    USE SIGNAL ;
    PORT
      LAYER Metal2 ;
        RECT  1133.08 0 1133.48 0.4 ;
    END
  END window_fault_o[31]
  PIN window_fault_o[3]
    DIRECTION OUTPUT ;
    USE SIGNAL ;
    PORT
      LAYER Metal2 ;
        RECT  649.24 0 649.64 0.4 ;
    END
  END window_fault_o[3]
  PIN window_fault_o[4]
    DIRECTION OUTPUT ;
    USE SIGNAL ;
    PORT
      LAYER Metal2 ;
        RECT  666.52 0 666.92 0.4 ;
    END
  END window_fault_o[4]
  PIN window_fault_o[5]
    DIRECTION OUTPUT ;
    USE SIGNAL ;
    PORT
      LAYER Metal2 ;
        RECT  683.8 0 684.2 0.4 ;
    END
  END window_fault_o[5]
  PIN window_fault_o[6]
    DIRECTION OUTPUT ;
    USE SIGNAL ;
    PORT
      LAYER Metal2 ;
        RECT  701.08 0 701.48 0.4 ;
    END
  END window_fault_o[6]
  PIN window_fault_o[7]
    DIRECTION OUTPUT ;
    USE SIGNAL ;
    PORT
      LAYER Metal2 ;
        RECT  718.36 0 718.76 0.4 ;
    END
  END window_fault_o[7]
  PIN window_fault_o[8]
    DIRECTION OUTPUT ;
    USE SIGNAL ;
    PORT
      LAYER Metal2 ;
        RECT  735.64 0 736.04 0.4 ;
    END
  END window_fault_o[8]
  PIN window_fault_o[9]
    DIRECTION OUTPUT ;
    USE SIGNAL ;
    PORT
      LAYER Metal2 ;
        RECT  752.92 0 753.32 0.4 ;
    END
  END window_fault_o[9]
  PIN window_o[0]
    DIRECTION OUTPUT ;
    USE SIGNAL ;
    PORT
      LAYER Metal3 ;
        RECT  1799.6 33.82 1800 34.22 ;
    END
  END window_o[0]
  PIN window_o[100]
    DIRECTION OUTPUT ;
    USE SIGNAL ;
    PORT
      LAYER Metal3 ;
        RECT  1799.6 789.82 1800 790.22 ;
    END
  END window_o[100]
  PIN window_o[101]
    DIRECTION OUTPUT ;
    USE SIGNAL ;
    PORT
      LAYER Metal3 ;
        RECT  1799.6 797.38 1800 797.78 ;
    END
  END window_o[101]
  PIN window_o[102]
    DIRECTION OUTPUT ;
    USE SIGNAL ;
    PORT
      LAYER Metal3 ;
        RECT  1799.6 804.94 1800 805.34 ;
    END
  END window_o[102]
  PIN window_o[103]
    DIRECTION OUTPUT ;
    USE SIGNAL ;
    PORT
      LAYER Metal3 ;
        RECT  1799.6 812.5 1800 812.9 ;
    END
  END window_o[103]
  PIN window_o[104]
    DIRECTION OUTPUT ;
    USE SIGNAL ;
    PORT
      LAYER Metal3 ;
        RECT  1799.6 820.06 1800 820.46 ;
    END
  END window_o[104]
  PIN window_o[105]
    DIRECTION OUTPUT ;
    USE SIGNAL ;
    PORT
      LAYER Metal3 ;
        RECT  1799.6 827.62 1800 828.02 ;
    END
  END window_o[105]
  PIN window_o[106]
    DIRECTION OUTPUT ;
    USE SIGNAL ;
    PORT
      LAYER Metal3 ;
        RECT  1799.6 835.18 1800 835.58 ;
    END
  END window_o[106]
  PIN window_o[107]
    DIRECTION OUTPUT ;
    USE SIGNAL ;
    PORT
      LAYER Metal3 ;
        RECT  1799.6 842.74 1800 843.14 ;
    END
  END window_o[107]
  PIN window_o[108]
    DIRECTION OUTPUT ;
    USE SIGNAL ;
    PORT
      LAYER Metal3 ;
        RECT  1799.6 850.3 1800 850.7 ;
    END
  END window_o[108]
  PIN window_o[109]
    DIRECTION OUTPUT ;
    USE SIGNAL ;
    PORT
      LAYER Metal3 ;
        RECT  1799.6 857.86 1800 858.26 ;
    END
  END window_o[109]
  PIN window_o[10]
    DIRECTION OUTPUT ;
    USE SIGNAL ;
    PORT
      LAYER Metal3 ;
        RECT  1799.6 109.42 1800 109.82 ;
    END
  END window_o[10]
  PIN window_o[110]
    DIRECTION OUTPUT ;
    USE SIGNAL ;
    PORT
      LAYER Metal3 ;
        RECT  1799.6 865.42 1800 865.82 ;
    END
  END window_o[110]
  PIN window_o[111]
    DIRECTION OUTPUT ;
    USE SIGNAL ;
    PORT
      LAYER Metal3 ;
        RECT  1799.6 872.98 1800 873.38 ;
    END
  END window_o[111]
  PIN window_o[112]
    DIRECTION OUTPUT ;
    USE SIGNAL ;
    PORT
      LAYER Metal3 ;
        RECT  1799.6 880.54 1800 880.94 ;
    END
  END window_o[112]
  PIN window_o[113]
    DIRECTION OUTPUT ;
    USE SIGNAL ;
    PORT
      LAYER Metal3 ;
        RECT  1799.6 888.1 1800 888.5 ;
    END
  END window_o[113]
  PIN window_o[114]
    DIRECTION OUTPUT ;
    USE SIGNAL ;
    PORT
      LAYER Metal3 ;
        RECT  1799.6 895.66 1800 896.06 ;
    END
  END window_o[114]
  PIN window_o[115]
    DIRECTION OUTPUT ;
    USE SIGNAL ;
    PORT
      LAYER Metal3 ;
        RECT  1799.6 903.22 1800 903.62 ;
    END
  END window_o[115]
  PIN window_o[116]
    DIRECTION OUTPUT ;
    USE SIGNAL ;
    PORT
      LAYER Metal3 ;
        RECT  1799.6 910.78 1800 911.18 ;
    END
  END window_o[116]
  PIN window_o[117]
    DIRECTION OUTPUT ;
    USE SIGNAL ;
    PORT
      LAYER Metal3 ;
        RECT  1799.6 918.34 1800 918.74 ;
    END
  END window_o[117]
  PIN window_o[118]
    DIRECTION OUTPUT ;
    USE SIGNAL ;
    PORT
      LAYER Metal3 ;
        RECT  1799.6 925.9 1800 926.3 ;
    END
  END window_o[118]
  PIN window_o[119]
    DIRECTION OUTPUT ;
    USE SIGNAL ;
    PORT
      LAYER Metal3 ;
        RECT  1799.6 933.46 1800 933.86 ;
    END
  END window_o[119]
  PIN window_o[11]
    DIRECTION OUTPUT ;
    USE SIGNAL ;
    PORT
      LAYER Metal3 ;
        RECT  1799.6 116.98 1800 117.38 ;
    END
  END window_o[11]
  PIN window_o[120]
    DIRECTION OUTPUT ;
    USE SIGNAL ;
    PORT
      LAYER Metal3 ;
        RECT  1799.6 941.02 1800 941.42 ;
    END
  END window_o[120]
  PIN window_o[121]
    DIRECTION OUTPUT ;
    USE SIGNAL ;
    PORT
      LAYER Metal3 ;
        RECT  1799.6 948.58 1800 948.98 ;
    END
  END window_o[121]
  PIN window_o[122]
    DIRECTION OUTPUT ;
    USE SIGNAL ;
    PORT
      LAYER Metal3 ;
        RECT  1799.6 956.14 1800 956.54 ;
    END
  END window_o[122]
  PIN window_o[123]
    DIRECTION OUTPUT ;
    USE SIGNAL ;
    PORT
      LAYER Metal3 ;
        RECT  1799.6 963.7 1800 964.1 ;
    END
  END window_o[123]
  PIN window_o[124]
    DIRECTION OUTPUT ;
    USE SIGNAL ;
    PORT
      LAYER Metal3 ;
        RECT  1799.6 971.26 1800 971.66 ;
    END
  END window_o[124]
  PIN window_o[125]
    DIRECTION OUTPUT ;
    USE SIGNAL ;
    PORT
      LAYER Metal3 ;
        RECT  1799.6 978.82 1800 979.22 ;
    END
  END window_o[125]
  PIN window_o[126]
    DIRECTION OUTPUT ;
    USE SIGNAL ;
    PORT
      LAYER Metal3 ;
        RECT  1799.6 986.38 1800 986.78 ;
    END
  END window_o[126]
  PIN window_o[127]
    DIRECTION OUTPUT ;
    USE SIGNAL ;
    PORT
      LAYER Metal3 ;
        RECT  1799.6 993.94 1800 994.34 ;
    END
  END window_o[127]
  PIN window_o[128]
    DIRECTION OUTPUT ;
    USE SIGNAL ;
    PORT
      LAYER Metal3 ;
        RECT  1799.6 1001.5 1800 1001.9 ;
    END
  END window_o[128]
  PIN window_o[129]
    DIRECTION OUTPUT ;
    USE SIGNAL ;
    PORT
      LAYER Metal3 ;
        RECT  1799.6 1009.06 1800 1009.46 ;
    END
  END window_o[129]
  PIN window_o[12]
    DIRECTION OUTPUT ;
    USE SIGNAL ;
    PORT
      LAYER Metal3 ;
        RECT  1799.6 124.54 1800 124.94 ;
    END
  END window_o[12]
  PIN window_o[130]
    DIRECTION OUTPUT ;
    USE SIGNAL ;
    PORT
      LAYER Metal3 ;
        RECT  1799.6 1016.62 1800 1017.02 ;
    END
  END window_o[130]
  PIN window_o[131]
    DIRECTION OUTPUT ;
    USE SIGNAL ;
    PORT
      LAYER Metal3 ;
        RECT  1799.6 1024.18 1800 1024.58 ;
    END
  END window_o[131]
  PIN window_o[132]
    DIRECTION OUTPUT ;
    USE SIGNAL ;
    PORT
      LAYER Metal3 ;
        RECT  1799.6 1031.74 1800 1032.14 ;
    END
  END window_o[132]
  PIN window_o[133]
    DIRECTION OUTPUT ;
    USE SIGNAL ;
    PORT
      LAYER Metal3 ;
        RECT  1799.6 1039.3 1800 1039.7 ;
    END
  END window_o[133]
  PIN window_o[134]
    DIRECTION OUTPUT ;
    USE SIGNAL ;
    PORT
      LAYER Metal3 ;
        RECT  1799.6 1046.86 1800 1047.26 ;
    END
  END window_o[134]
  PIN window_o[135]
    DIRECTION OUTPUT ;
    USE SIGNAL ;
    PORT
      LAYER Metal3 ;
        RECT  1799.6 1054.42 1800 1054.82 ;
    END
  END window_o[135]
  PIN window_o[136]
    DIRECTION OUTPUT ;
    USE SIGNAL ;
    PORT
      LAYER Metal3 ;
        RECT  1799.6 1061.98 1800 1062.38 ;
    END
  END window_o[136]
  PIN window_o[137]
    DIRECTION OUTPUT ;
    USE SIGNAL ;
    PORT
      LAYER Metal3 ;
        RECT  1799.6 1069.54 1800 1069.94 ;
    END
  END window_o[137]
  PIN window_o[138]
    DIRECTION OUTPUT ;
    USE SIGNAL ;
    PORT
      LAYER Metal3 ;
        RECT  1799.6 1077.1 1800 1077.5 ;
    END
  END window_o[138]
  PIN window_o[139]
    DIRECTION OUTPUT ;
    USE SIGNAL ;
    PORT
      LAYER Metal3 ;
        RECT  1799.6 1084.66 1800 1085.06 ;
    END
  END window_o[139]
  PIN window_o[13]
    DIRECTION OUTPUT ;
    USE SIGNAL ;
    PORT
      LAYER Metal3 ;
        RECT  1799.6 132.1 1800 132.5 ;
    END
  END window_o[13]
  PIN window_o[140]
    DIRECTION OUTPUT ;
    USE SIGNAL ;
    PORT
      LAYER Metal3 ;
        RECT  1799.6 1092.22 1800 1092.62 ;
    END
  END window_o[140]
  PIN window_o[141]
    DIRECTION OUTPUT ;
    USE SIGNAL ;
    PORT
      LAYER Metal3 ;
        RECT  1799.6 1099.78 1800 1100.18 ;
    END
  END window_o[141]
  PIN window_o[142]
    DIRECTION OUTPUT ;
    USE SIGNAL ;
    PORT
      LAYER Metal3 ;
        RECT  1799.6 1107.34 1800 1107.74 ;
    END
  END window_o[142]
  PIN window_o[143]
    DIRECTION OUTPUT ;
    USE SIGNAL ;
    PORT
      LAYER Metal3 ;
        RECT  1799.6 1114.9 1800 1115.3 ;
    END
  END window_o[143]
  PIN window_o[144]
    DIRECTION OUTPUT ;
    USE SIGNAL ;
    PORT
      LAYER Metal3 ;
        RECT  1799.6 1122.46 1800 1122.86 ;
    END
  END window_o[144]
  PIN window_o[145]
    DIRECTION OUTPUT ;
    USE SIGNAL ;
    PORT
      LAYER Metal3 ;
        RECT  1799.6 1130.02 1800 1130.42 ;
    END
  END window_o[145]
  PIN window_o[146]
    DIRECTION OUTPUT ;
    USE SIGNAL ;
    PORT
      LAYER Metal3 ;
        RECT  1799.6 1137.58 1800 1137.98 ;
    END
  END window_o[146]
  PIN window_o[147]
    DIRECTION OUTPUT ;
    USE SIGNAL ;
    PORT
      LAYER Metal3 ;
        RECT  1799.6 1145.14 1800 1145.54 ;
    END
  END window_o[147]
  PIN window_o[148]
    DIRECTION OUTPUT ;
    USE SIGNAL ;
    PORT
      LAYER Metal3 ;
        RECT  1799.6 1152.7 1800 1153.1 ;
    END
  END window_o[148]
  PIN window_o[149]
    DIRECTION OUTPUT ;
    USE SIGNAL ;
    PORT
      LAYER Metal3 ;
        RECT  1799.6 1160.26 1800 1160.66 ;
    END
  END window_o[149]
  PIN window_o[14]
    DIRECTION OUTPUT ;
    USE SIGNAL ;
    PORT
      LAYER Metal3 ;
        RECT  1799.6 139.66 1800 140.06 ;
    END
  END window_o[14]
  PIN window_o[150]
    DIRECTION OUTPUT ;
    USE SIGNAL ;
    PORT
      LAYER Metal3 ;
        RECT  1799.6 1167.82 1800 1168.22 ;
    END
  END window_o[150]
  PIN window_o[151]
    DIRECTION OUTPUT ;
    USE SIGNAL ;
    PORT
      LAYER Metal3 ;
        RECT  1799.6 1175.38 1800 1175.78 ;
    END
  END window_o[151]
  PIN window_o[152]
    DIRECTION OUTPUT ;
    USE SIGNAL ;
    PORT
      LAYER Metal3 ;
        RECT  1799.6 1182.94 1800 1183.34 ;
    END
  END window_o[152]
  PIN window_o[153]
    DIRECTION OUTPUT ;
    USE SIGNAL ;
    PORT
      LAYER Metal3 ;
        RECT  1799.6 1190.5 1800 1190.9 ;
    END
  END window_o[153]
  PIN window_o[154]
    DIRECTION OUTPUT ;
    USE SIGNAL ;
    PORT
      LAYER Metal3 ;
        RECT  1799.6 1198.06 1800 1198.46 ;
    END
  END window_o[154]
  PIN window_o[155]
    DIRECTION OUTPUT ;
    USE SIGNAL ;
    PORT
      LAYER Metal3 ;
        RECT  1799.6 1205.62 1800 1206.02 ;
    END
  END window_o[155]
  PIN window_o[156]
    DIRECTION OUTPUT ;
    USE SIGNAL ;
    PORT
      LAYER Metal3 ;
        RECT  1799.6 1213.18 1800 1213.58 ;
    END
  END window_o[156]
  PIN window_o[157]
    DIRECTION OUTPUT ;
    USE SIGNAL ;
    PORT
      LAYER Metal3 ;
        RECT  1799.6 1220.74 1800 1221.14 ;
    END
  END window_o[157]
  PIN window_o[158]
    DIRECTION OUTPUT ;
    USE SIGNAL ;
    PORT
      LAYER Metal3 ;
        RECT  1799.6 1228.3 1800 1228.7 ;
    END
  END window_o[158]
  PIN window_o[159]
    DIRECTION OUTPUT ;
    USE SIGNAL ;
    PORT
      LAYER Metal3 ;
        RECT  1799.6 1235.86 1800 1236.26 ;
    END
  END window_o[159]
  PIN window_o[15]
    DIRECTION OUTPUT ;
    USE SIGNAL ;
    PORT
      LAYER Metal3 ;
        RECT  1799.6 147.22 1800 147.62 ;
    END
  END window_o[15]
  PIN window_o[160]
    DIRECTION OUTPUT ;
    USE SIGNAL ;
    PORT
      LAYER Metal3 ;
        RECT  1799.6 1243.42 1800 1243.82 ;
    END
  END window_o[160]
  PIN window_o[161]
    DIRECTION OUTPUT ;
    USE SIGNAL ;
    PORT
      LAYER Metal3 ;
        RECT  1799.6 1250.98 1800 1251.38 ;
    END
  END window_o[161]
  PIN window_o[162]
    DIRECTION OUTPUT ;
    USE SIGNAL ;
    PORT
      LAYER Metal3 ;
        RECT  1799.6 1258.54 1800 1258.94 ;
    END
  END window_o[162]
  PIN window_o[163]
    DIRECTION OUTPUT ;
    USE SIGNAL ;
    PORT
      LAYER Metal3 ;
        RECT  1799.6 1266.1 1800 1266.5 ;
    END
  END window_o[163]
  PIN window_o[164]
    DIRECTION OUTPUT ;
    USE SIGNAL ;
    PORT
      LAYER Metal3 ;
        RECT  1799.6 1273.66 1800 1274.06 ;
    END
  END window_o[164]
  PIN window_o[165]
    DIRECTION OUTPUT ;
    USE SIGNAL ;
    PORT
      LAYER Metal3 ;
        RECT  1799.6 1281.22 1800 1281.62 ;
    END
  END window_o[165]
  PIN window_o[166]
    DIRECTION OUTPUT ;
    USE SIGNAL ;
    PORT
      LAYER Metal3 ;
        RECT  1799.6 1288.78 1800 1289.18 ;
    END
  END window_o[166]
  PIN window_o[167]
    DIRECTION OUTPUT ;
    USE SIGNAL ;
    PORT
      LAYER Metal3 ;
        RECT  1799.6 1296.34 1800 1296.74 ;
    END
  END window_o[167]
  PIN window_o[168]
    DIRECTION OUTPUT ;
    USE SIGNAL ;
    PORT
      LAYER Metal3 ;
        RECT  1799.6 1303.9 1800 1304.3 ;
    END
  END window_o[168]
  PIN window_o[169]
    DIRECTION OUTPUT ;
    USE SIGNAL ;
    PORT
      LAYER Metal3 ;
        RECT  1799.6 1311.46 1800 1311.86 ;
    END
  END window_o[169]
  PIN window_o[16]
    DIRECTION OUTPUT ;
    USE SIGNAL ;
    PORT
      LAYER Metal3 ;
        RECT  1799.6 154.78 1800 155.18 ;
    END
  END window_o[16]
  PIN window_o[170]
    DIRECTION OUTPUT ;
    USE SIGNAL ;
    PORT
      LAYER Metal3 ;
        RECT  1799.6 1319.02 1800 1319.42 ;
    END
  END window_o[170]
  PIN window_o[171]
    DIRECTION OUTPUT ;
    USE SIGNAL ;
    PORT
      LAYER Metal3 ;
        RECT  1799.6 1326.58 1800 1326.98 ;
    END
  END window_o[171]
  PIN window_o[172]
    DIRECTION OUTPUT ;
    USE SIGNAL ;
    PORT
      LAYER Metal3 ;
        RECT  1799.6 1334.14 1800 1334.54 ;
    END
  END window_o[172]
  PIN window_o[173]
    DIRECTION OUTPUT ;
    USE SIGNAL ;
    PORT
      LAYER Metal3 ;
        RECT  1799.6 1341.7 1800 1342.1 ;
    END
  END window_o[173]
  PIN window_o[174]
    DIRECTION OUTPUT ;
    USE SIGNAL ;
    PORT
      LAYER Metal3 ;
        RECT  1799.6 1349.26 1800 1349.66 ;
    END
  END window_o[174]
  PIN window_o[175]
    DIRECTION OUTPUT ;
    USE SIGNAL ;
    PORT
      LAYER Metal3 ;
        RECT  1799.6 1356.82 1800 1357.22 ;
    END
  END window_o[175]
  PIN window_o[176]
    DIRECTION OUTPUT ;
    USE SIGNAL ;
    PORT
      LAYER Metal3 ;
        RECT  1799.6 1364.38 1800 1364.78 ;
    END
  END window_o[176]
  PIN window_o[177]
    DIRECTION OUTPUT ;
    USE SIGNAL ;
    PORT
      LAYER Metal3 ;
        RECT  1799.6 1371.94 1800 1372.34 ;
    END
  END window_o[177]
  PIN window_o[178]
    DIRECTION OUTPUT ;
    USE SIGNAL ;
    PORT
      LAYER Metal3 ;
        RECT  1799.6 1379.5 1800 1379.9 ;
    END
  END window_o[178]
  PIN window_o[179]
    DIRECTION OUTPUT ;
    USE SIGNAL ;
    PORT
      LAYER Metal3 ;
        RECT  1799.6 1387.06 1800 1387.46 ;
    END
  END window_o[179]
  PIN window_o[17]
    DIRECTION OUTPUT ;
    USE SIGNAL ;
    PORT
      LAYER Metal3 ;
        RECT  1799.6 162.34 1800 162.74 ;
    END
  END window_o[17]
  PIN window_o[180]
    DIRECTION OUTPUT ;
    USE SIGNAL ;
    PORT
      LAYER Metal3 ;
        RECT  1799.6 1394.62 1800 1395.02 ;
    END
  END window_o[180]
  PIN window_o[181]
    DIRECTION OUTPUT ;
    USE SIGNAL ;
    PORT
      LAYER Metal3 ;
        RECT  1799.6 1402.18 1800 1402.58 ;
    END
  END window_o[181]
  PIN window_o[182]
    DIRECTION OUTPUT ;
    USE SIGNAL ;
    PORT
      LAYER Metal3 ;
        RECT  1799.6 1409.74 1800 1410.14 ;
    END
  END window_o[182]
  PIN window_o[183]
    DIRECTION OUTPUT ;
    USE SIGNAL ;
    PORT
      LAYER Metal3 ;
        RECT  1799.6 1417.3 1800 1417.7 ;
    END
  END window_o[183]
  PIN window_o[184]
    DIRECTION OUTPUT ;
    USE SIGNAL ;
    PORT
      LAYER Metal3 ;
        RECT  1799.6 1424.86 1800 1425.26 ;
    END
  END window_o[184]
  PIN window_o[185]
    DIRECTION OUTPUT ;
    USE SIGNAL ;
    PORT
      LAYER Metal3 ;
        RECT  1799.6 1432.42 1800 1432.82 ;
    END
  END window_o[185]
  PIN window_o[186]
    DIRECTION OUTPUT ;
    USE SIGNAL ;
    PORT
      LAYER Metal3 ;
        RECT  1799.6 1439.98 1800 1440.38 ;
    END
  END window_o[186]
  PIN window_o[187]
    DIRECTION OUTPUT ;
    USE SIGNAL ;
    PORT
      LAYER Metal3 ;
        RECT  1799.6 1447.54 1800 1447.94 ;
    END
  END window_o[187]
  PIN window_o[188]
    DIRECTION OUTPUT ;
    USE SIGNAL ;
    PORT
      LAYER Metal3 ;
        RECT  1799.6 1455.1 1800 1455.5 ;
    END
  END window_o[188]
  PIN window_o[189]
    DIRECTION OUTPUT ;
    USE SIGNAL ;
    PORT
      LAYER Metal3 ;
        RECT  1799.6 1462.66 1800 1463.06 ;
    END
  END window_o[189]
  PIN window_o[18]
    DIRECTION OUTPUT ;
    USE SIGNAL ;
    PORT
      LAYER Metal3 ;
        RECT  1799.6 169.9 1800 170.3 ;
    END
  END window_o[18]
  PIN window_o[190]
    DIRECTION OUTPUT ;
    USE SIGNAL ;
    PORT
      LAYER Metal3 ;
        RECT  1799.6 1470.22 1800 1470.62 ;
    END
  END window_o[190]
  PIN window_o[191]
    DIRECTION OUTPUT ;
    USE SIGNAL ;
    PORT
      LAYER Metal3 ;
        RECT  1799.6 1477.78 1800 1478.18 ;
    END
  END window_o[191]
  PIN window_o[192]
    DIRECTION OUTPUT ;
    USE SIGNAL ;
    PORT
      LAYER Metal3 ;
        RECT  1799.6 1485.34 1800 1485.74 ;
    END
  END window_o[192]
  PIN window_o[193]
    DIRECTION OUTPUT ;
    USE SIGNAL ;
    PORT
      LAYER Metal3 ;
        RECT  1799.6 1492.9 1800 1493.3 ;
    END
  END window_o[193]
  PIN window_o[194]
    DIRECTION OUTPUT ;
    USE SIGNAL ;
    PORT
      LAYER Metal3 ;
        RECT  1799.6 1500.46 1800 1500.86 ;
    END
  END window_o[194]
  PIN window_o[195]
    DIRECTION OUTPUT ;
    USE SIGNAL ;
    PORT
      LAYER Metal3 ;
        RECT  1799.6 1508.02 1800 1508.42 ;
    END
  END window_o[195]
  PIN window_o[196]
    DIRECTION OUTPUT ;
    USE SIGNAL ;
    PORT
      LAYER Metal3 ;
        RECT  1799.6 1515.58 1800 1515.98 ;
    END
  END window_o[196]
  PIN window_o[197]
    DIRECTION OUTPUT ;
    USE SIGNAL ;
    PORT
      LAYER Metal3 ;
        RECT  1799.6 1523.14 1800 1523.54 ;
    END
  END window_o[197]
  PIN window_o[198]
    DIRECTION OUTPUT ;
    USE SIGNAL ;
    PORT
      LAYER Metal3 ;
        RECT  1799.6 1530.7 1800 1531.1 ;
    END
  END window_o[198]
  PIN window_o[199]
    DIRECTION OUTPUT ;
    USE SIGNAL ;
    PORT
      LAYER Metal3 ;
        RECT  1799.6 1538.26 1800 1538.66 ;
    END
  END window_o[199]
  PIN window_o[19]
    DIRECTION OUTPUT ;
    USE SIGNAL ;
    PORT
      LAYER Metal3 ;
        RECT  1799.6 177.46 1800 177.86 ;
    END
  END window_o[19]
  PIN window_o[1]
    DIRECTION OUTPUT ;
    USE SIGNAL ;
    PORT
      LAYER Metal3 ;
        RECT  1799.6 41.38 1800 41.78 ;
    END
  END window_o[1]
  PIN window_o[200]
    DIRECTION OUTPUT ;
    USE SIGNAL ;
    PORT
      LAYER Metal3 ;
        RECT  1799.6 1545.82 1800 1546.22 ;
    END
  END window_o[200]
  PIN window_o[201]
    DIRECTION OUTPUT ;
    USE SIGNAL ;
    PORT
      LAYER Metal3 ;
        RECT  1799.6 1553.38 1800 1553.78 ;
    END
  END window_o[201]
  PIN window_o[202]
    DIRECTION OUTPUT ;
    USE SIGNAL ;
    PORT
      LAYER Metal3 ;
        RECT  1799.6 1560.94 1800 1561.34 ;
    END
  END window_o[202]
  PIN window_o[203]
    DIRECTION OUTPUT ;
    USE SIGNAL ;
    PORT
      LAYER Metal3 ;
        RECT  1799.6 1568.5 1800 1568.9 ;
    END
  END window_o[203]
  PIN window_o[204]
    DIRECTION OUTPUT ;
    USE SIGNAL ;
    PORT
      LAYER Metal3 ;
        RECT  1799.6 1576.06 1800 1576.46 ;
    END
  END window_o[204]
  PIN window_o[205]
    DIRECTION OUTPUT ;
    USE SIGNAL ;
    PORT
      LAYER Metal3 ;
        RECT  1799.6 1583.62 1800 1584.02 ;
    END
  END window_o[205]
  PIN window_o[206]
    DIRECTION OUTPUT ;
    USE SIGNAL ;
    PORT
      LAYER Metal3 ;
        RECT  1799.6 1591.18 1800 1591.58 ;
    END
  END window_o[206]
  PIN window_o[207]
    DIRECTION OUTPUT ;
    USE SIGNAL ;
    PORT
      LAYER Metal3 ;
        RECT  1799.6 1598.74 1800 1599.14 ;
    END
  END window_o[207]
  PIN window_o[208]
    DIRECTION OUTPUT ;
    USE SIGNAL ;
    PORT
      LAYER Metal3 ;
        RECT  1799.6 1606.3 1800 1606.7 ;
    END
  END window_o[208]
  PIN window_o[209]
    DIRECTION OUTPUT ;
    USE SIGNAL ;
    PORT
      LAYER Metal3 ;
        RECT  1799.6 1613.86 1800 1614.26 ;
    END
  END window_o[209]
  PIN window_o[20]
    DIRECTION OUTPUT ;
    USE SIGNAL ;
    PORT
      LAYER Metal3 ;
        RECT  1799.6 185.02 1800 185.42 ;
    END
  END window_o[20]
  PIN window_o[210]
    DIRECTION OUTPUT ;
    USE SIGNAL ;
    PORT
      LAYER Metal3 ;
        RECT  1799.6 1621.42 1800 1621.82 ;
    END
  END window_o[210]
  PIN window_o[211]
    DIRECTION OUTPUT ;
    USE SIGNAL ;
    PORT
      LAYER Metal3 ;
        RECT  1799.6 1628.98 1800 1629.38 ;
    END
  END window_o[211]
  PIN window_o[212]
    DIRECTION OUTPUT ;
    USE SIGNAL ;
    PORT
      LAYER Metal3 ;
        RECT  1799.6 1636.54 1800 1636.94 ;
    END
  END window_o[212]
  PIN window_o[213]
    DIRECTION OUTPUT ;
    USE SIGNAL ;
    PORT
      LAYER Metal3 ;
        RECT  1799.6 1644.1 1800 1644.5 ;
    END
  END window_o[213]
  PIN window_o[214]
    DIRECTION OUTPUT ;
    USE SIGNAL ;
    PORT
      LAYER Metal3 ;
        RECT  1799.6 1651.66 1800 1652.06 ;
    END
  END window_o[214]
  PIN window_o[215]
    DIRECTION OUTPUT ;
    USE SIGNAL ;
    PORT
      LAYER Metal3 ;
        RECT  1799.6 1659.22 1800 1659.62 ;
    END
  END window_o[215]
  PIN window_o[216]
    DIRECTION OUTPUT ;
    USE SIGNAL ;
    PORT
      LAYER Metal3 ;
        RECT  1799.6 1666.78 1800 1667.18 ;
    END
  END window_o[216]
  PIN window_o[217]
    DIRECTION OUTPUT ;
    USE SIGNAL ;
    PORT
      LAYER Metal3 ;
        RECT  1799.6 1674.34 1800 1674.74 ;
    END
  END window_o[217]
  PIN window_o[218]
    DIRECTION OUTPUT ;
    USE SIGNAL ;
    PORT
      LAYER Metal3 ;
        RECT  1799.6 1681.9 1800 1682.3 ;
    END
  END window_o[218]
  PIN window_o[219]
    DIRECTION OUTPUT ;
    USE SIGNAL ;
    PORT
      LAYER Metal3 ;
        RECT  1799.6 1689.46 1800 1689.86 ;
    END
  END window_o[219]
  PIN window_o[21]
    DIRECTION OUTPUT ;
    USE SIGNAL ;
    PORT
      LAYER Metal3 ;
        RECT  1799.6 192.58 1800 192.98 ;
    END
  END window_o[21]
  PIN window_o[220]
    DIRECTION OUTPUT ;
    USE SIGNAL ;
    PORT
      LAYER Metal3 ;
        RECT  1799.6 1697.02 1800 1697.42 ;
    END
  END window_o[220]
  PIN window_o[221]
    DIRECTION OUTPUT ;
    USE SIGNAL ;
    PORT
      LAYER Metal3 ;
        RECT  1799.6 1704.58 1800 1704.98 ;
    END
  END window_o[221]
  PIN window_o[222]
    DIRECTION OUTPUT ;
    USE SIGNAL ;
    PORT
      LAYER Metal3 ;
        RECT  1799.6 1712.14 1800 1712.54 ;
    END
  END window_o[222]
  PIN window_o[223]
    DIRECTION OUTPUT ;
    USE SIGNAL ;
    PORT
      LAYER Metal3 ;
        RECT  1799.6 1719.7 1800 1720.1 ;
    END
  END window_o[223]
  PIN window_o[224]
    DIRECTION OUTPUT ;
    USE SIGNAL ;
    PORT
      LAYER Metal3 ;
        RECT  1799.6 1727.26 1800 1727.66 ;
    END
  END window_o[224]
  PIN window_o[225]
    DIRECTION OUTPUT ;
    USE SIGNAL ;
    PORT
      LAYER Metal3 ;
        RECT  1799.6 1734.82 1800 1735.22 ;
    END
  END window_o[225]
  PIN window_o[226]
    DIRECTION OUTPUT ;
    USE SIGNAL ;
    PORT
      LAYER Metal3 ;
        RECT  1799.6 1742.38 1800 1742.78 ;
    END
  END window_o[226]
  PIN window_o[227]
    DIRECTION OUTPUT ;
    USE SIGNAL ;
    PORT
      LAYER Metal3 ;
        RECT  1799.6 1749.94 1800 1750.34 ;
    END
  END window_o[227]
  PIN window_o[228]
    DIRECTION OUTPUT ;
    USE SIGNAL ;
    PORT
      LAYER Metal3 ;
        RECT  1799.6 1757.5 1800 1757.9 ;
    END
  END window_o[228]
  PIN window_o[229]
    DIRECTION OUTPUT ;
    USE SIGNAL ;
    PORT
      LAYER Metal3 ;
        RECT  1799.6 1765.06 1800 1765.46 ;
    END
  END window_o[229]
  PIN window_o[22]
    DIRECTION OUTPUT ;
    USE SIGNAL ;
    PORT
      LAYER Metal3 ;
        RECT  1799.6 200.14 1800 200.54 ;
    END
  END window_o[22]
  PIN window_o[230]
    DIRECTION OUTPUT ;
    USE SIGNAL ;
    PORT
      LAYER Metal3 ;
        RECT  1799.6 1772.62 1800 1773.02 ;
    END
  END window_o[230]
  PIN window_o[231]
    DIRECTION OUTPUT ;
    USE SIGNAL ;
    PORT
      LAYER Metal3 ;
        RECT  1799.6 1780.18 1800 1780.58 ;
    END
  END window_o[231]
  PIN window_o[232]
    DIRECTION OUTPUT ;
    USE SIGNAL ;
    PORT
      LAYER Metal3 ;
        RECT  1799.6 1787.74 1800 1788.14 ;
    END
  END window_o[232]
  PIN window_o[233]
    DIRECTION OUTPUT ;
    USE SIGNAL ;
    PORT
      LAYER Metal3 ;
        RECT  1799.6 1795.3 1800 1795.7 ;
    END
  END window_o[233]
  PIN window_o[234]
    DIRECTION OUTPUT ;
    USE SIGNAL ;
    PORT
      LAYER Metal3 ;
        RECT  1799.6 1802.86 1800 1803.26 ;
    END
  END window_o[234]
  PIN window_o[235]
    DIRECTION OUTPUT ;
    USE SIGNAL ;
    PORT
      LAYER Metal3 ;
        RECT  1799.6 1810.42 1800 1810.82 ;
    END
  END window_o[235]
  PIN window_o[236]
    DIRECTION OUTPUT ;
    USE SIGNAL ;
    PORT
      LAYER Metal3 ;
        RECT  1799.6 1817.98 1800 1818.38 ;
    END
  END window_o[236]
  PIN window_o[237]
    DIRECTION OUTPUT ;
    USE SIGNAL ;
    PORT
      LAYER Metal3 ;
        RECT  1799.6 1825.54 1800 1825.94 ;
    END
  END window_o[237]
  PIN window_o[238]
    DIRECTION OUTPUT ;
    USE SIGNAL ;
    PORT
      LAYER Metal3 ;
        RECT  1799.6 1833.1 1800 1833.5 ;
    END
  END window_o[238]
  PIN window_o[239]
    DIRECTION OUTPUT ;
    USE SIGNAL ;
    PORT
      LAYER Metal3 ;
        RECT  1799.6 1840.66 1800 1841.06 ;
    END
  END window_o[239]
  PIN window_o[23]
    DIRECTION OUTPUT ;
    USE SIGNAL ;
    PORT
      LAYER Metal3 ;
        RECT  1799.6 207.7 1800 208.1 ;
    END
  END window_o[23]
  PIN window_o[240]
    DIRECTION OUTPUT ;
    USE SIGNAL ;
    PORT
      LAYER Metal3 ;
        RECT  1799.6 1848.22 1800 1848.62 ;
    END
  END window_o[240]
  PIN window_o[241]
    DIRECTION OUTPUT ;
    USE SIGNAL ;
    PORT
      LAYER Metal3 ;
        RECT  1799.6 1855.78 1800 1856.18 ;
    END
  END window_o[241]
  PIN window_o[242]
    DIRECTION OUTPUT ;
    USE SIGNAL ;
    PORT
      LAYER Metal3 ;
        RECT  1799.6 1863.34 1800 1863.74 ;
    END
  END window_o[242]
  PIN window_o[243]
    DIRECTION OUTPUT ;
    USE SIGNAL ;
    PORT
      LAYER Metal3 ;
        RECT  1799.6 1870.9 1800 1871.3 ;
    END
  END window_o[243]
  PIN window_o[244]
    DIRECTION OUTPUT ;
    USE SIGNAL ;
    PORT
      LAYER Metal3 ;
        RECT  1799.6 1878.46 1800 1878.86 ;
    END
  END window_o[244]
  PIN window_o[245]
    DIRECTION OUTPUT ;
    USE SIGNAL ;
    PORT
      LAYER Metal3 ;
        RECT  1799.6 1886.02 1800 1886.42 ;
    END
  END window_o[245]
  PIN window_o[246]
    DIRECTION OUTPUT ;
    USE SIGNAL ;
    PORT
      LAYER Metal3 ;
        RECT  1799.6 1893.58 1800 1893.98 ;
    END
  END window_o[246]
  PIN window_o[247]
    DIRECTION OUTPUT ;
    USE SIGNAL ;
    PORT
      LAYER Metal3 ;
        RECT  1799.6 1901.14 1800 1901.54 ;
    END
  END window_o[247]
  PIN window_o[248]
    DIRECTION OUTPUT ;
    USE SIGNAL ;
    PORT
      LAYER Metal3 ;
        RECT  1799.6 1908.7 1800 1909.1 ;
    END
  END window_o[248]
  PIN window_o[249]
    DIRECTION OUTPUT ;
    USE SIGNAL ;
    PORT
      LAYER Metal3 ;
        RECT  1799.6 1916.26 1800 1916.66 ;
    END
  END window_o[249]
  PIN window_o[24]
    DIRECTION OUTPUT ;
    USE SIGNAL ;
    PORT
      LAYER Metal3 ;
        RECT  1799.6 215.26 1800 215.66 ;
    END
  END window_o[24]
  PIN window_o[250]
    DIRECTION OUTPUT ;
    USE SIGNAL ;
    PORT
      LAYER Metal3 ;
        RECT  1799.6 1923.82 1800 1924.22 ;
    END
  END window_o[250]
  PIN window_o[251]
    DIRECTION OUTPUT ;
    USE SIGNAL ;
    PORT
      LAYER Metal3 ;
        RECT  1799.6 1931.38 1800 1931.78 ;
    END
  END window_o[251]
  PIN window_o[252]
    DIRECTION OUTPUT ;
    USE SIGNAL ;
    PORT
      LAYER Metal3 ;
        RECT  1799.6 1938.94 1800 1939.34 ;
    END
  END window_o[252]
  PIN window_o[253]
    DIRECTION OUTPUT ;
    USE SIGNAL ;
    PORT
      LAYER Metal3 ;
        RECT  1799.6 1946.5 1800 1946.9 ;
    END
  END window_o[253]
  PIN window_o[254]
    DIRECTION OUTPUT ;
    USE SIGNAL ;
    PORT
      LAYER Metal3 ;
        RECT  1799.6 1954.06 1800 1954.46 ;
    END
  END window_o[254]
  PIN window_o[255]
    DIRECTION OUTPUT ;
    USE SIGNAL ;
    PORT
      LAYER Metal3 ;
        RECT  1799.6 1961.62 1800 1962.02 ;
    END
  END window_o[255]
  PIN window_o[25]
    DIRECTION OUTPUT ;
    USE SIGNAL ;
    PORT
      LAYER Metal3 ;
        RECT  1799.6 222.82 1800 223.22 ;
    END
  END window_o[25]
  PIN window_o[26]
    DIRECTION OUTPUT ;
    USE SIGNAL ;
    PORT
      LAYER Metal3 ;
        RECT  1799.6 230.38 1800 230.78 ;
    END
  END window_o[26]
  PIN window_o[27]
    DIRECTION OUTPUT ;
    USE SIGNAL ;
    PORT
      LAYER Metal3 ;
        RECT  1799.6 237.94 1800 238.34 ;
    END
  END window_o[27]
  PIN window_o[28]
    DIRECTION OUTPUT ;
    USE SIGNAL ;
    PORT
      LAYER Metal3 ;
        RECT  1799.6 245.5 1800 245.9 ;
    END
  END window_o[28]
  PIN window_o[29]
    DIRECTION OUTPUT ;
    USE SIGNAL ;
    PORT
      LAYER Metal3 ;
        RECT  1799.6 253.06 1800 253.46 ;
    END
  END window_o[29]
  PIN window_o[2]
    DIRECTION OUTPUT ;
    USE SIGNAL ;
    PORT
      LAYER Metal3 ;
        RECT  1799.6 48.94 1800 49.34 ;
    END
  END window_o[2]
  PIN window_o[30]
    DIRECTION OUTPUT ;
    USE SIGNAL ;
    PORT
      LAYER Metal3 ;
        RECT  1799.6 260.62 1800 261.02 ;
    END
  END window_o[30]
  PIN window_o[31]
    DIRECTION OUTPUT ;
    USE SIGNAL ;
    PORT
      LAYER Metal3 ;
        RECT  1799.6 268.18 1800 268.58 ;
    END
  END window_o[31]
  PIN window_o[32]
    DIRECTION OUTPUT ;
    USE SIGNAL ;
    PORT
      LAYER Metal3 ;
        RECT  1799.6 275.74 1800 276.14 ;
    END
  END window_o[32]
  PIN window_o[33]
    DIRECTION OUTPUT ;
    USE SIGNAL ;
    PORT
      LAYER Metal3 ;
        RECT  1799.6 283.3 1800 283.7 ;
    END
  END window_o[33]
  PIN window_o[34]
    DIRECTION OUTPUT ;
    USE SIGNAL ;
    PORT
      LAYER Metal3 ;
        RECT  1799.6 290.86 1800 291.26 ;
    END
  END window_o[34]
  PIN window_o[35]
    DIRECTION OUTPUT ;
    USE SIGNAL ;
    PORT
      LAYER Metal3 ;
        RECT  1799.6 298.42 1800 298.82 ;
    END
  END window_o[35]
  PIN window_o[36]
    DIRECTION OUTPUT ;
    USE SIGNAL ;
    PORT
      LAYER Metal3 ;
        RECT  1799.6 305.98 1800 306.38 ;
    END
  END window_o[36]
  PIN window_o[37]
    DIRECTION OUTPUT ;
    USE SIGNAL ;
    PORT
      LAYER Metal3 ;
        RECT  1799.6 313.54 1800 313.94 ;
    END
  END window_o[37]
  PIN window_o[38]
    DIRECTION OUTPUT ;
    USE SIGNAL ;
    PORT
      LAYER Metal3 ;
        RECT  1799.6 321.1 1800 321.5 ;
    END
  END window_o[38]
  PIN window_o[39]
    DIRECTION OUTPUT ;
    USE SIGNAL ;
    PORT
      LAYER Metal3 ;
        RECT  1799.6 328.66 1800 329.06 ;
    END
  END window_o[39]
  PIN window_o[3]
    DIRECTION OUTPUT ;
    USE SIGNAL ;
    PORT
      LAYER Metal3 ;
        RECT  1799.6 56.5 1800 56.9 ;
    END
  END window_o[3]
  PIN window_o[40]
    DIRECTION OUTPUT ;
    USE SIGNAL ;
    PORT
      LAYER Metal3 ;
        RECT  1799.6 336.22 1800 336.62 ;
    END
  END window_o[40]
  PIN window_o[41]
    DIRECTION OUTPUT ;
    USE SIGNAL ;
    PORT
      LAYER Metal3 ;
        RECT  1799.6 343.78 1800 344.18 ;
    END
  END window_o[41]
  PIN window_o[42]
    DIRECTION OUTPUT ;
    USE SIGNAL ;
    PORT
      LAYER Metal3 ;
        RECT  1799.6 351.34 1800 351.74 ;
    END
  END window_o[42]
  PIN window_o[43]
    DIRECTION OUTPUT ;
    USE SIGNAL ;
    PORT
      LAYER Metal3 ;
        RECT  1799.6 358.9 1800 359.3 ;
    END
  END window_o[43]
  PIN window_o[44]
    DIRECTION OUTPUT ;
    USE SIGNAL ;
    PORT
      LAYER Metal3 ;
        RECT  1799.6 366.46 1800 366.86 ;
    END
  END window_o[44]
  PIN window_o[45]
    DIRECTION OUTPUT ;
    USE SIGNAL ;
    PORT
      LAYER Metal3 ;
        RECT  1799.6 374.02 1800 374.42 ;
    END
  END window_o[45]
  PIN window_o[46]
    DIRECTION OUTPUT ;
    USE SIGNAL ;
    PORT
      LAYER Metal3 ;
        RECT  1799.6 381.58 1800 381.98 ;
    END
  END window_o[46]
  PIN window_o[47]
    DIRECTION OUTPUT ;
    USE SIGNAL ;
    PORT
      LAYER Metal3 ;
        RECT  1799.6 389.14 1800 389.54 ;
    END
  END window_o[47]
  PIN window_o[48]
    DIRECTION OUTPUT ;
    USE SIGNAL ;
    PORT
      LAYER Metal3 ;
        RECT  1799.6 396.7 1800 397.1 ;
    END
  END window_o[48]
  PIN window_o[49]
    DIRECTION OUTPUT ;
    USE SIGNAL ;
    PORT
      LAYER Metal3 ;
        RECT  1799.6 404.26 1800 404.66 ;
    END
  END window_o[49]
  PIN window_o[4]
    DIRECTION OUTPUT ;
    USE SIGNAL ;
    PORT
      LAYER Metal3 ;
        RECT  1799.6 64.06 1800 64.46 ;
    END
  END window_o[4]
  PIN window_o[50]
    DIRECTION OUTPUT ;
    USE SIGNAL ;
    PORT
      LAYER Metal3 ;
        RECT  1799.6 411.82 1800 412.22 ;
    END
  END window_o[50]
  PIN window_o[51]
    DIRECTION OUTPUT ;
    USE SIGNAL ;
    PORT
      LAYER Metal3 ;
        RECT  1799.6 419.38 1800 419.78 ;
    END
  END window_o[51]
  PIN window_o[52]
    DIRECTION OUTPUT ;
    USE SIGNAL ;
    PORT
      LAYER Metal3 ;
        RECT  1799.6 426.94 1800 427.34 ;
    END
  END window_o[52]
  PIN window_o[53]
    DIRECTION OUTPUT ;
    USE SIGNAL ;
    PORT
      LAYER Metal3 ;
        RECT  1799.6 434.5 1800 434.9 ;
    END
  END window_o[53]
  PIN window_o[54]
    DIRECTION OUTPUT ;
    USE SIGNAL ;
    PORT
      LAYER Metal3 ;
        RECT  1799.6 442.06 1800 442.46 ;
    END
  END window_o[54]
  PIN window_o[55]
    DIRECTION OUTPUT ;
    USE SIGNAL ;
    PORT
      LAYER Metal3 ;
        RECT  1799.6 449.62 1800 450.02 ;
    END
  END window_o[55]
  PIN window_o[56]
    DIRECTION OUTPUT ;
    USE SIGNAL ;
    PORT
      LAYER Metal3 ;
        RECT  1799.6 457.18 1800 457.58 ;
    END
  END window_o[56]
  PIN window_o[57]
    DIRECTION OUTPUT ;
    USE SIGNAL ;
    PORT
      LAYER Metal3 ;
        RECT  1799.6 464.74 1800 465.14 ;
    END
  END window_o[57]
  PIN window_o[58]
    DIRECTION OUTPUT ;
    USE SIGNAL ;
    PORT
      LAYER Metal3 ;
        RECT  1799.6 472.3 1800 472.7 ;
    END
  END window_o[58]
  PIN window_o[59]
    DIRECTION OUTPUT ;
    USE SIGNAL ;
    PORT
      LAYER Metal3 ;
        RECT  1799.6 479.86 1800 480.26 ;
    END
  END window_o[59]
  PIN window_o[5]
    DIRECTION OUTPUT ;
    USE SIGNAL ;
    PORT
      LAYER Metal3 ;
        RECT  1799.6 71.62 1800 72.02 ;
    END
  END window_o[5]
  PIN window_o[60]
    DIRECTION OUTPUT ;
    USE SIGNAL ;
    PORT
      LAYER Metal3 ;
        RECT  1799.6 487.42 1800 487.82 ;
    END
  END window_o[60]
  PIN window_o[61]
    DIRECTION OUTPUT ;
    USE SIGNAL ;
    PORT
      LAYER Metal3 ;
        RECT  1799.6 494.98 1800 495.38 ;
    END
  END window_o[61]
  PIN window_o[62]
    DIRECTION OUTPUT ;
    USE SIGNAL ;
    PORT
      LAYER Metal3 ;
        RECT  1799.6 502.54 1800 502.94 ;
    END
  END window_o[62]
  PIN window_o[63]
    DIRECTION OUTPUT ;
    USE SIGNAL ;
    PORT
      LAYER Metal3 ;
        RECT  1799.6 510.1 1800 510.5 ;
    END
  END window_o[63]
  PIN window_o[64]
    DIRECTION OUTPUT ;
    USE SIGNAL ;
    PORT
      LAYER Metal3 ;
        RECT  1799.6 517.66 1800 518.06 ;
    END
  END window_o[64]
  PIN window_o[65]
    DIRECTION OUTPUT ;
    USE SIGNAL ;
    PORT
      LAYER Metal3 ;
        RECT  1799.6 525.22 1800 525.62 ;
    END
  END window_o[65]
  PIN window_o[66]
    DIRECTION OUTPUT ;
    USE SIGNAL ;
    PORT
      LAYER Metal3 ;
        RECT  1799.6 532.78 1800 533.18 ;
    END
  END window_o[66]
  PIN window_o[67]
    DIRECTION OUTPUT ;
    USE SIGNAL ;
    PORT
      LAYER Metal3 ;
        RECT  1799.6 540.34 1800 540.74 ;
    END
  END window_o[67]
  PIN window_o[68]
    DIRECTION OUTPUT ;
    USE SIGNAL ;
    PORT
      LAYER Metal3 ;
        RECT  1799.6 547.9 1800 548.3 ;
    END
  END window_o[68]
  PIN window_o[69]
    DIRECTION OUTPUT ;
    USE SIGNAL ;
    PORT
      LAYER Metal3 ;
        RECT  1799.6 555.46 1800 555.86 ;
    END
  END window_o[69]
  PIN window_o[6]
    DIRECTION OUTPUT ;
    USE SIGNAL ;
    PORT
      LAYER Metal3 ;
        RECT  1799.6 79.18 1800 79.58 ;
    END
  END window_o[6]
  PIN window_o[70]
    DIRECTION OUTPUT ;
    USE SIGNAL ;
    PORT
      LAYER Metal3 ;
        RECT  1799.6 563.02 1800 563.42 ;
    END
  END window_o[70]
  PIN window_o[71]
    DIRECTION OUTPUT ;
    USE SIGNAL ;
    PORT
      LAYER Metal3 ;
        RECT  1799.6 570.58 1800 570.98 ;
    END
  END window_o[71]
  PIN window_o[72]
    DIRECTION OUTPUT ;
    USE SIGNAL ;
    PORT
      LAYER Metal3 ;
        RECT  1799.6 578.14 1800 578.54 ;
    END
  END window_o[72]
  PIN window_o[73]
    DIRECTION OUTPUT ;
    USE SIGNAL ;
    PORT
      LAYER Metal3 ;
        RECT  1799.6 585.7 1800 586.1 ;
    END
  END window_o[73]
  PIN window_o[74]
    DIRECTION OUTPUT ;
    USE SIGNAL ;
    PORT
      LAYER Metal3 ;
        RECT  1799.6 593.26 1800 593.66 ;
    END
  END window_o[74]
  PIN window_o[75]
    DIRECTION OUTPUT ;
    USE SIGNAL ;
    PORT
      LAYER Metal3 ;
        RECT  1799.6 600.82 1800 601.22 ;
    END
  END window_o[75]
  PIN window_o[76]
    DIRECTION OUTPUT ;
    USE SIGNAL ;
    PORT
      LAYER Metal3 ;
        RECT  1799.6 608.38 1800 608.78 ;
    END
  END window_o[76]
  PIN window_o[77]
    DIRECTION OUTPUT ;
    USE SIGNAL ;
    PORT
      LAYER Metal3 ;
        RECT  1799.6 615.94 1800 616.34 ;
    END
  END window_o[77]
  PIN window_o[78]
    DIRECTION OUTPUT ;
    USE SIGNAL ;
    PORT
      LAYER Metal3 ;
        RECT  1799.6 623.5 1800 623.9 ;
    END
  END window_o[78]
  PIN window_o[79]
    DIRECTION OUTPUT ;
    USE SIGNAL ;
    PORT
      LAYER Metal3 ;
        RECT  1799.6 631.06 1800 631.46 ;
    END
  END window_o[79]
  PIN window_o[7]
    DIRECTION OUTPUT ;
    USE SIGNAL ;
    PORT
      LAYER Metal3 ;
        RECT  1799.6 86.74 1800 87.14 ;
    END
  END window_o[7]
  PIN window_o[80]
    DIRECTION OUTPUT ;
    USE SIGNAL ;
    PORT
      LAYER Metal3 ;
        RECT  1799.6 638.62 1800 639.02 ;
    END
  END window_o[80]
  PIN window_o[81]
    DIRECTION OUTPUT ;
    USE SIGNAL ;
    PORT
      LAYER Metal3 ;
        RECT  1799.6 646.18 1800 646.58 ;
    END
  END window_o[81]
  PIN window_o[82]
    DIRECTION OUTPUT ;
    USE SIGNAL ;
    PORT
      LAYER Metal3 ;
        RECT  1799.6 653.74 1800 654.14 ;
    END
  END window_o[82]
  PIN window_o[83]
    DIRECTION OUTPUT ;
    USE SIGNAL ;
    PORT
      LAYER Metal3 ;
        RECT  1799.6 661.3 1800 661.7 ;
    END
  END window_o[83]
  PIN window_o[84]
    DIRECTION OUTPUT ;
    USE SIGNAL ;
    PORT
      LAYER Metal3 ;
        RECT  1799.6 668.86 1800 669.26 ;
    END
  END window_o[84]
  PIN window_o[85]
    DIRECTION OUTPUT ;
    USE SIGNAL ;
    PORT
      LAYER Metal3 ;
        RECT  1799.6 676.42 1800 676.82 ;
    END
  END window_o[85]
  PIN window_o[86]
    DIRECTION OUTPUT ;
    USE SIGNAL ;
    PORT
      LAYER Metal3 ;
        RECT  1799.6 683.98 1800 684.38 ;
    END
  END window_o[86]
  PIN window_o[87]
    DIRECTION OUTPUT ;
    USE SIGNAL ;
    PORT
      LAYER Metal3 ;
        RECT  1799.6 691.54 1800 691.94 ;
    END
  END window_o[87]
  PIN window_o[88]
    DIRECTION OUTPUT ;
    USE SIGNAL ;
    PORT
      LAYER Metal3 ;
        RECT  1799.6 699.1 1800 699.5 ;
    END
  END window_o[88]
  PIN window_o[89]
    DIRECTION OUTPUT ;
    USE SIGNAL ;
    PORT
      LAYER Metal3 ;
        RECT  1799.6 706.66 1800 707.06 ;
    END
  END window_o[89]
  PIN window_o[8]
    DIRECTION OUTPUT ;
    USE SIGNAL ;
    PORT
      LAYER Metal3 ;
        RECT  1799.6 94.3 1800 94.7 ;
    END
  END window_o[8]
  PIN window_o[90]
    DIRECTION OUTPUT ;
    USE SIGNAL ;
    PORT
      LAYER Metal3 ;
        RECT  1799.6 714.22 1800 714.62 ;
    END
  END window_o[90]
  PIN window_o[91]
    DIRECTION OUTPUT ;
    USE SIGNAL ;
    PORT
      LAYER Metal3 ;
        RECT  1799.6 721.78 1800 722.18 ;
    END
  END window_o[91]
  PIN window_o[92]
    DIRECTION OUTPUT ;
    USE SIGNAL ;
    PORT
      LAYER Metal3 ;
        RECT  1799.6 729.34 1800 729.74 ;
    END
  END window_o[92]
  PIN window_o[93]
    DIRECTION OUTPUT ;
    USE SIGNAL ;
    PORT
      LAYER Metal3 ;
        RECT  1799.6 736.9 1800 737.3 ;
    END
  END window_o[93]
  PIN window_o[94]
    DIRECTION OUTPUT ;
    USE SIGNAL ;
    PORT
      LAYER Metal3 ;
        RECT  1799.6 744.46 1800 744.86 ;
    END
  END window_o[94]
  PIN window_o[95]
    DIRECTION OUTPUT ;
    USE SIGNAL ;
    PORT
      LAYER Metal3 ;
        RECT  1799.6 752.02 1800 752.42 ;
    END
  END window_o[95]
  PIN window_o[96]
    DIRECTION OUTPUT ;
    USE SIGNAL ;
    PORT
      LAYER Metal3 ;
        RECT  1799.6 759.58 1800 759.98 ;
    END
  END window_o[96]
  PIN window_o[97]
    DIRECTION OUTPUT ;
    USE SIGNAL ;
    PORT
      LAYER Metal3 ;
        RECT  1799.6 767.14 1800 767.54 ;
    END
  END window_o[97]
  PIN window_o[98]
    DIRECTION OUTPUT ;
    USE SIGNAL ;
    PORT
      LAYER Metal3 ;
        RECT  1799.6 774.7 1800 775.1 ;
    END
  END window_o[98]
  PIN window_o[99]
    DIRECTION OUTPUT ;
    USE SIGNAL ;
    PORT
      LAYER Metal3 ;
        RECT  1799.6 782.26 1800 782.66 ;
    END
  END window_o[99]
  PIN window_o[9]
    DIRECTION OUTPUT ;
    USE SIGNAL ;
    PORT
      LAYER Metal3 ;
        RECT  1799.6 101.86 1800 102.26 ;
    END
  END window_o[9]
  PIN window_pc_o[0]
    DIRECTION OUTPUT ;
    USE SIGNAL ;
    PORT
      LAYER Metal2 ;
        RECT  1254.04 0 1254.44 0.4 ;
    END
  END window_pc_o[0]
  PIN window_pc_o[10]
    DIRECTION OUTPUT ;
    USE SIGNAL ;
    PORT
      LAYER Metal2 ;
        RECT  1426.84 0 1427.24 0.4 ;
    END
  END window_pc_o[10]
  PIN window_pc_o[11]
    DIRECTION OUTPUT ;
    USE SIGNAL ;
    PORT
      LAYER Metal2 ;
        RECT  1444.12 0 1444.52 0.4 ;
    END
  END window_pc_o[11]
  PIN window_pc_o[12]
    DIRECTION OUTPUT ;
    USE SIGNAL ;
    PORT
      LAYER Metal2 ;
        RECT  1461.4 0 1461.8 0.4 ;
    END
  END window_pc_o[12]
  PIN window_pc_o[13]
    DIRECTION OUTPUT ;
    USE SIGNAL ;
    PORT
      LAYER Metal2 ;
        RECT  1478.68 0 1479.08 0.4 ;
    END
  END window_pc_o[13]
  PIN window_pc_o[14]
    DIRECTION OUTPUT ;
    USE SIGNAL ;
    PORT
      LAYER Metal2 ;
        RECT  1495.96 0 1496.36 0.4 ;
    END
  END window_pc_o[14]
  PIN window_pc_o[15]
    DIRECTION OUTPUT ;
    USE SIGNAL ;
    PORT
      LAYER Metal2 ;
        RECT  1513.24 0 1513.64 0.4 ;
    END
  END window_pc_o[15]
  PIN window_pc_o[16]
    DIRECTION OUTPUT ;
    USE SIGNAL ;
    PORT
      LAYER Metal2 ;
        RECT  1530.52 0 1530.92 0.4 ;
    END
  END window_pc_o[16]
  PIN window_pc_o[17]
    DIRECTION OUTPUT ;
    USE SIGNAL ;
    PORT
      LAYER Metal2 ;
        RECT  1547.8 0 1548.2 0.4 ;
    END
  END window_pc_o[17]
  PIN window_pc_o[18]
    DIRECTION OUTPUT ;
    USE SIGNAL ;
    PORT
      LAYER Metal2 ;
        RECT  1565.08 0 1565.48 0.4 ;
    END
  END window_pc_o[18]
  PIN window_pc_o[19]
    DIRECTION OUTPUT ;
    USE SIGNAL ;
    PORT
      LAYER Metal2 ;
        RECT  1582.36 0 1582.76 0.4 ;
    END
  END window_pc_o[19]
  PIN window_pc_o[1]
    DIRECTION OUTPUT ;
    USE SIGNAL ;
    PORT
      LAYER Metal2 ;
        RECT  1271.32 0 1271.72 0.4 ;
    END
  END window_pc_o[1]
  PIN window_pc_o[20]
    DIRECTION OUTPUT ;
    USE SIGNAL ;
    PORT
      LAYER Metal2 ;
        RECT  1599.64 0 1600.04 0.4 ;
    END
  END window_pc_o[20]
  PIN window_pc_o[21]
    DIRECTION OUTPUT ;
    USE SIGNAL ;
    PORT
      LAYER Metal2 ;
        RECT  1616.92 0 1617.32 0.4 ;
    END
  END window_pc_o[21]
  PIN window_pc_o[22]
    DIRECTION OUTPUT ;
    USE SIGNAL ;
    PORT
      LAYER Metal2 ;
        RECT  1634.2 0 1634.6 0.4 ;
    END
  END window_pc_o[22]
  PIN window_pc_o[23]
    DIRECTION OUTPUT ;
    USE SIGNAL ;
    PORT
      LAYER Metal2 ;
        RECT  1651.48 0 1651.88 0.4 ;
    END
  END window_pc_o[23]
  PIN window_pc_o[24]
    DIRECTION OUTPUT ;
    USE SIGNAL ;
    PORT
      LAYER Metal2 ;
        RECT  1668.76 0 1669.16 0.4 ;
    END
  END window_pc_o[24]
  PIN window_pc_o[25]
    DIRECTION OUTPUT ;
    USE SIGNAL ;
    PORT
      LAYER Metal2 ;
        RECT  1686.04 0 1686.44 0.4 ;
    END
  END window_pc_o[25]
  PIN window_pc_o[26]
    DIRECTION OUTPUT ;
    USE SIGNAL ;
    PORT
      LAYER Metal2 ;
        RECT  1703.32 0 1703.72 0.4 ;
    END
  END window_pc_o[26]
  PIN window_pc_o[27]
    DIRECTION OUTPUT ;
    USE SIGNAL ;
    PORT
      LAYER Metal2 ;
        RECT  1720.6 0 1721 0.4 ;
    END
  END window_pc_o[27]
  PIN window_pc_o[28]
    DIRECTION OUTPUT ;
    USE SIGNAL ;
    PORT
      LAYER Metal2 ;
        RECT  1737.88 0 1738.28 0.4 ;
    END
  END window_pc_o[28]
  PIN window_pc_o[29]
    DIRECTION OUTPUT ;
    USE SIGNAL ;
    PORT
      LAYER Metal2 ;
        RECT  1755.16 0 1755.56 0.4 ;
    END
  END window_pc_o[29]
  PIN window_pc_o[2]
    DIRECTION OUTPUT ;
    USE SIGNAL ;
    PORT
      LAYER Metal2 ;
        RECT  1288.6 0 1289 0.4 ;
    END
  END window_pc_o[2]
  PIN window_pc_o[30]
    DIRECTION OUTPUT ;
    USE SIGNAL ;
    PORT
      LAYER Metal2 ;
        RECT  1772.44 0 1772.84 0.4 ;
    END
  END window_pc_o[30]
  PIN window_pc_o[31]
    DIRECTION OUTPUT ;
    USE SIGNAL ;
    PORT
      LAYER Metal2 ;
        RECT  1789.72 0 1790.12 0.4 ;
    END
  END window_pc_o[31]
  PIN window_pc_o[3]
    DIRECTION OUTPUT ;
    USE SIGNAL ;
    PORT
      LAYER Metal2 ;
        RECT  1305.88 0 1306.28 0.4 ;
    END
  END window_pc_o[3]
  PIN window_pc_o[4]
    DIRECTION OUTPUT ;
    USE SIGNAL ;
    PORT
      LAYER Metal2 ;
        RECT  1323.16 0 1323.56 0.4 ;
    END
  END window_pc_o[4]
  PIN window_pc_o[5]
    DIRECTION OUTPUT ;
    USE SIGNAL ;
    PORT
      LAYER Metal2 ;
        RECT  1340.44 0 1340.84 0.4 ;
    END
  END window_pc_o[5]
  PIN window_pc_o[6]
    DIRECTION OUTPUT ;
    USE SIGNAL ;
    PORT
      LAYER Metal2 ;
        RECT  1357.72 0 1358.12 0.4 ;
    END
  END window_pc_o[6]
  PIN window_pc_o[7]
    DIRECTION OUTPUT ;
    USE SIGNAL ;
    PORT
      LAYER Metal2 ;
        RECT  1375 0 1375.4 0.4 ;
    END
  END window_pc_o[7]
  PIN window_pc_o[8]
    DIRECTION OUTPUT ;
    USE SIGNAL ;
    PORT
      LAYER Metal2 ;
        RECT  1392.28 0 1392.68 0.4 ;
    END
  END window_pc_o[8]
  PIN window_pc_o[9]
    DIRECTION OUTPUT ;
    USE SIGNAL ;
    PORT
      LAYER Metal2 ;
        RECT  1409.56 0 1409.96 0.4 ;
    END
  END window_pc_o[9]
  PIN VPWR
    DIRECTION INOUT ;
    USE POWER ;
    PORT
      LAYER TopMetal1 ;
        RECT  865.13 835.84 1616.39 837.48 ;
        RECT  15.13 1435.84 766.39 1437.48 ;
        RECT  865.13 1435.84 1616.39 1437.48 ;
        RECT  15.13 835.84 766.39 837.48 ;
        RECT  5.76 2024.12 1794.24 2026.12 ;
        RECT  5.76 1974.12 1794.24 1976.12 ;
        RECT  5.76 1924.12 1794.24 1926.12 ;
        RECT  5.76 1874.12 1794.24 1876.12 ;
        RECT  5.76 1824.12 1794.24 1826.12 ;
        RECT  5.76 1774.12 1794.24 1776.12 ;
        RECT  5.76 1724.12 1794.24 1726.12 ;
        RECT  5.76 1674.12 1794.24 1676.12 ;
        RECT  5.76 1624.12 1794.24 1626.12 ;
        RECT  5.76 1574.12 1794.24 1576.12 ;
        RECT  5.76 1524.12 1794.24 1526.12 ;
        RECT  5.76 1474.12 1794.24 1476.12 ;
        RECT  5.76 1424.12 1794.24 1426.12 ;
        RECT  5.76 1374.12 1794.24 1376.12 ;
        RECT  5.76 1324.12 1794.24 1326.12 ;
        RECT  5.76 1274.12 1794.24 1276.12 ;
        RECT  5.76 1224.12 1794.24 1226.12 ;
        RECT  5.76 1174.12 1794.24 1176.12 ;
        RECT  5.76 1124.12 1794.24 1126.12 ;
        RECT  5.76 1074.12 1794.24 1076.12 ;
        RECT  5.76 1024.12 1794.24 1026.12 ;
        RECT  5.76 974.12 1794.24 976.12 ;
        RECT  5.76 924.12 1794.24 926.12 ;
        RECT  5.76 874.12 1794.24 876.12 ;
        RECT  5.76 824.12 1794.24 826.12 ;
        RECT  5.76 774.12 1794.24 776.12 ;
        RECT  5.76 724.12 1794.24 726.12 ;
        RECT  5.76 674.12 1794.24 676.12 ;
        RECT  5.76 624.12 1794.24 626.12 ;
        RECT  5.76 574.12 1794.24 576.12 ;
        RECT  5.76 524.12 1794.24 526.12 ;
        RECT  5.76 474.12 1794.24 476.12 ;
        RECT  5.76 424.12 1794.24 426.12 ;
        RECT  5.76 374.12 1794.24 376.12 ;
        RECT  5.76 324.12 1794.24 326.12 ;
        RECT  5.76 274.12 1794.24 276.12 ;
        RECT  5.76 224.12 1794.24 226.12 ;
        RECT  5.76 174.12 1794.24 176.12 ;
        RECT  5.76 124.12 1794.24 126.12 ;
        RECT  5.76 74.12 1794.24 76.12 ;
        RECT  5.76 24.12 1794.24 26.12 ;
      LAYER Metal4 ;
        RECT  1765.26 14.9 1766.26 2033.86 ;
        RECT  1715.26 14.9 1716.26 2033.86 ;
        RECT  1665.26 14.9 1666.26 2033.86 ;
        RECT  1615.26 14.9 1616.26 2033.86 ;
        RECT  1565.26 1680.05 1566.26 2033.86 ;
        RECT  1565.26 1430.12 1566.26 1439.32 ;
        RECT  1565.26 1080.05 1566.26 1189.39 ;
        RECT  1565.26 830.12 1566.26 839.32 ;
        RECT  1565.26 479.84 1566.26 589.39 ;
        RECT  1565.26 14.9 1566.26 239.32 ;
        RECT  1515.26 1680.05 1516.26 2033.86 ;
        RECT  1515.26 1430.12 1516.26 1439.32 ;
        RECT  1515.26 1080.05 1516.26 1189.39 ;
        RECT  1515.26 830.12 1516.26 839.32 ;
        RECT  1515.26 479.84 1516.26 589.39 ;
        RECT  1515.26 14.9 1516.26 239.32 ;
        RECT  1465.26 1679.81 1466.26 2033.86 ;
        RECT  1465.26 1429.88 1466.26 1439.56 ;
        RECT  1465.26 1079.81 1466.26 1189.63 ;
        RECT  1465.26 829.88 1466.26 839.56 ;
        RECT  1465.26 479.81 1466.26 589.63 ;
        RECT  1465.26 14.9 1466.26 239.56 ;
        RECT  1415.26 1680.05 1416.26 2033.86 ;
        RECT  1415.26 1430.12 1416.26 1439.32 ;
        RECT  1415.26 1080.05 1416.26 1189.39 ;
        RECT  1415.26 830.12 1416.26 839.32 ;
        RECT  1415.26 479.84 1416.26 589.39 ;
        RECT  1415.26 14.9 1416.26 239.32 ;
        RECT  1365.26 1680.05 1366.26 2033.86 ;
        RECT  1365.26 1430.12 1366.26 1439.32 ;
        RECT  1365.26 1080.05 1366.26 1189.39 ;
        RECT  1365.26 830.12 1366.26 839.32 ;
        RECT  1365.26 479.84 1366.26 589.39 ;
        RECT  1365.26 14.9 1366.26 239.32 ;
        RECT  1315.26 1679.81 1316.26 2033.86 ;
        RECT  1315.26 1429.88 1316.26 1439.56 ;
        RECT  1315.26 1079.81 1316.26 1189.63 ;
        RECT  1315.26 829.88 1316.26 839.56 ;
        RECT  1315.26 479.81 1316.26 589.63 ;
        RECT  1315.26 14.9 1316.26 239.56 ;
        RECT  1265.26 1680.05 1266.26 2033.86 ;
        RECT  1265.26 1430.12 1266.26 1439.32 ;
        RECT  1265.26 1080.05 1266.26 1189.39 ;
        RECT  1265.26 830.12 1266.26 839.32 ;
        RECT  1265.26 479.84 1266.26 589.39 ;
        RECT  1265.26 14.9 1266.26 239.32 ;
        RECT  1215.26 1680.05 1216.26 2033.86 ;
        RECT  1215.26 1430.12 1216.26 1439.32 ;
        RECT  1215.26 1080.05 1216.26 1189.39 ;
        RECT  1215.26 830.12 1216.26 839.32 ;
        RECT  1215.26 479.84 1216.26 589.39 ;
        RECT  1215.26 14.9 1216.26 239.32 ;
        RECT  1165.26 1680.05 1166.26 2033.86 ;
        RECT  1165.26 1430.12 1166.26 1439.32 ;
        RECT  1165.26 1080.05 1166.26 1189.39 ;
        RECT  1165.26 830.12 1166.26 839.32 ;
        RECT  1165.26 479.84 1166.26 589.39 ;
        RECT  1165.26 14.9 1166.26 239.32 ;
        RECT  1115.26 1679.81 1116.26 2033.86 ;
        RECT  1115.26 1429.88 1116.26 1439.56 ;
        RECT  1115.26 1079.81 1116.26 1189.63 ;
        RECT  1115.26 829.88 1116.26 839.56 ;
        RECT  1115.26 479.81 1116.26 589.63 ;
        RECT  1115.26 14.9 1116.26 239.56 ;
        RECT  1065.26 1680.05 1066.26 2033.86 ;
        RECT  1065.26 1430.12 1066.26 1439.32 ;
        RECT  1065.26 1080.05 1066.26 1189.39 ;
        RECT  1065.26 830.12 1066.26 839.32 ;
        RECT  1065.26 479.84 1066.26 589.39 ;
        RECT  1065.26 14.9 1066.26 239.32 ;
        RECT  1015.26 1680.05 1016.26 2033.86 ;
        RECT  1015.26 1430.12 1016.26 1439.32 ;
        RECT  1015.26 1080.05 1016.26 1189.39 ;
        RECT  1015.26 830.12 1016.26 839.32 ;
        RECT  1015.26 479.84 1016.26 589.39 ;
        RECT  1015.26 14.9 1016.26 239.32 ;
        RECT  965.26 1679.81 966.26 2033.86 ;
        RECT  965.26 1429.88 966.26 1439.56 ;
        RECT  965.26 1079.81 966.26 1189.63 ;
        RECT  965.26 829.88 966.26 839.56 ;
        RECT  965.26 479.81 966.26 589.63 ;
        RECT  965.26 14.9 966.26 239.56 ;
        RECT  915.26 1680.05 916.26 2033.86 ;
        RECT  915.26 1430.12 916.26 1439.32 ;
        RECT  915.26 1080.05 916.26 1189.39 ;
        RECT  915.26 830.12 916.26 839.32 ;
        RECT  915.26 479.84 916.26 589.39 ;
        RECT  915.26 14.9 916.26 239.32 ;
        RECT  865.26 14.9 866.26 2033.86 ;
        RECT  815.26 14.9 816.26 2033.86 ;
        RECT  765.26 14.9 766.26 2033.86 ;
        RECT  715.26 1680.05 716.26 1789.39 ;
        RECT  715.26 1430.12 716.26 1439.32 ;
        RECT  715.26 1080.05 716.26 1189.39 ;
        RECT  715.26 830.12 716.26 839.32 ;
        RECT  715.26 479.84 716.26 589.39 ;
        RECT  715.26 14.9 716.26 239.32 ;
        RECT  665.26 1680.05 666.26 1789.39 ;
        RECT  665.26 1430.12 666.26 1439.32 ;
        RECT  665.26 1080.05 666.26 1189.39 ;
        RECT  665.26 830.12 666.26 839.32 ;
        RECT  665.26 479.84 666.26 589.39 ;
        RECT  665.26 14.9 666.26 239.32 ;
        RECT  615.26 1679.81 616.26 1789.63 ;
        RECT  615.26 1429.88 616.26 1439.56 ;
        RECT  615.26 1079.81 616.26 1189.63 ;
        RECT  615.26 829.88 616.26 839.56 ;
        RECT  615.26 479.81 616.26 589.63 ;
        RECT  615.26 14.9 616.26 239.56 ;
        RECT  565.26 1680.05 566.26 1789.39 ;
        RECT  565.26 1430.12 566.26 1439.32 ;
        RECT  565.26 1080.05 566.26 1189.39 ;
        RECT  565.26 830.12 566.26 839.32 ;
        RECT  565.26 479.84 566.26 589.39 ;
        RECT  565.26 14.9 566.26 239.32 ;
        RECT  515.26 1680.05 516.26 1789.39 ;
        RECT  515.26 1430.12 516.26 1439.32 ;
        RECT  515.26 1080.05 516.26 1189.39 ;
        RECT  515.26 830.12 516.26 839.32 ;
        RECT  515.26 479.84 516.26 589.39 ;
        RECT  515.26 14.9 516.26 239.32 ;
        RECT  465.26 1679.81 466.26 1789.63 ;
        RECT  465.26 1429.88 466.26 1439.56 ;
        RECT  465.26 1079.81 466.26 1189.63 ;
        RECT  465.26 829.88 466.26 839.56 ;
        RECT  465.26 479.81 466.26 589.63 ;
        RECT  465.26 14.9 466.26 239.56 ;
        RECT  415.26 1680.05 416.26 1789.39 ;
        RECT  415.26 1430.12 416.26 1439.32 ;
        RECT  415.26 1080.05 416.26 1189.39 ;
        RECT  415.26 830.12 416.26 839.32 ;
        RECT  415.26 479.84 416.26 589.39 ;
        RECT  415.26 14.9 416.26 239.32 ;
        RECT  365.26 1680.05 366.26 1789.39 ;
        RECT  365.26 1430.12 366.26 1439.32 ;
        RECT  365.26 1080.05 366.26 1189.39 ;
        RECT  365.26 830.12 366.26 839.32 ;
        RECT  365.26 479.84 366.26 589.39 ;
        RECT  365.26 14.9 366.26 239.32 ;
        RECT  315.26 1680.05 316.26 1789.39 ;
        RECT  315.26 1430.12 316.26 1439.32 ;
        RECT  315.26 1080.05 316.26 1189.39 ;
        RECT  315.26 830.12 316.26 839.32 ;
        RECT  315.26 479.84 316.26 589.39 ;
        RECT  315.26 14.9 316.26 239.32 ;
        RECT  265.26 1679.81 266.26 1789.63 ;
        RECT  265.26 1429.88 266.26 1439.56 ;
        RECT  265.26 1079.81 266.26 1189.63 ;
        RECT  265.26 829.88 266.26 839.56 ;
        RECT  265.26 479.81 266.26 589.63 ;
        RECT  265.26 14.9 266.26 239.56 ;
        RECT  215.26 1680.05 216.26 1789.39 ;
        RECT  215.26 1430.12 216.26 1439.32 ;
        RECT  215.26 1080.05 216.26 1189.39 ;
        RECT  215.26 830.12 216.26 839.32 ;
        RECT  215.26 479.84 216.26 589.39 ;
        RECT  215.26 14.9 216.26 239.32 ;
        RECT  165.26 1680.05 166.26 1789.39 ;
        RECT  165.26 1430.12 166.26 1439.32 ;
        RECT  165.26 1080.05 166.26 1189.39 ;
        RECT  165.26 830.12 166.26 839.32 ;
        RECT  165.26 479.84 166.26 589.39 ;
        RECT  165.26 14.9 166.26 239.32 ;
        RECT  115.26 1679.81 116.26 1789.63 ;
        RECT  115.26 1429.88 116.26 1439.56 ;
        RECT  115.26 1079.81 116.26 1189.63 ;
        RECT  115.26 829.88 116.26 839.56 ;
        RECT  115.26 479.81 116.26 589.63 ;
        RECT  115.26 14.9 116.26 239.56 ;
        RECT  65.26 1680.05 66.26 1789.39 ;
        RECT  65.26 1430.12 66.26 1439.32 ;
        RECT  65.26 1080.05 66.26 1189.39 ;
        RECT  65.26 830.12 66.26 839.32 ;
        RECT  65.26 479.84 66.26 589.39 ;
        RECT  65.26 14.9 66.26 239.32 ;
        RECT  15.26 14.9 16.26 2033.86 ;
    END
  END VPWR
  PIN VGND
    DIRECTION INOUT ;
    USE GROUND ;
    PORT
      LAYER TopMetal1 ;
        RECT  5.76 2030.12 1794.24 2032.12 ;
        RECT  5.76 1980.12 1794.24 1982.12 ;
        RECT  5.76 1930.12 1794.24 1932.12 ;
        RECT  5.76 1880.12 1794.24 1882.12 ;
        RECT  5.76 1830.12 1794.24 1832.12 ;
        RECT  5.76 1780.12 1794.24 1782.12 ;
        RECT  5.76 1730.12 1794.24 1732.12 ;
        RECT  5.76 1680.12 1794.24 1682.12 ;
        RECT  5.76 1630.12 1794.24 1632.12 ;
        RECT  5.76 1580.12 1794.24 1582.12 ;
        RECT  5.76 1530.12 1794.24 1532.12 ;
        RECT  5.76 1480.12 1794.24 1482.12 ;
        RECT  5.76 1430.12 1794.24 1432.12 ;
        RECT  5.76 1380.12 1794.24 1382.12 ;
        RECT  5.76 1330.12 1794.24 1332.12 ;
        RECT  5.76 1280.12 1794.24 1282.12 ;
        RECT  5.76 1230.12 1794.24 1232.12 ;
        RECT  5.76 1180.12 1794.24 1182.12 ;
        RECT  5.76 1130.12 1794.24 1132.12 ;
        RECT  5.76 1080.12 1794.24 1082.12 ;
        RECT  5.76 1030.12 1794.24 1032.12 ;
        RECT  5.76 980.12 1794.24 982.12 ;
        RECT  5.76 930.12 1794.24 932.12 ;
        RECT  5.76 880.12 1794.24 882.12 ;
        RECT  5.76 830.12 1794.24 832.12 ;
        RECT  5.76 780.12 1794.24 782.12 ;
        RECT  5.76 730.12 1794.24 732.12 ;
        RECT  5.76 680.12 1794.24 682.12 ;
        RECT  5.76 630.12 1794.24 632.12 ;
        RECT  5.76 580.12 1794.24 582.12 ;
        RECT  5.76 530.12 1794.24 532.12 ;
        RECT  5.76 480.12 1794.24 482.12 ;
        RECT  5.76 430.12 1794.24 432.12 ;
        RECT  5.76 380.12 1794.24 382.12 ;
        RECT  5.76 330.12 1794.24 332.12 ;
        RECT  5.76 280.12 1794.24 282.12 ;
        RECT  5.76 230.12 1794.24 232.12 ;
        RECT  5.76 180.12 1794.24 182.12 ;
        RECT  5.76 130.12 1794.24 132.12 ;
        RECT  5.76 80.12 1794.24 82.12 ;
        RECT  5.76 30.12 1794.24 32.12 ;
      LAYER Metal4 ;
        RECT  1768.26 14.9 1769.26 2033.86 ;
        RECT  1718.26 14.9 1719.26 2033.86 ;
        RECT  1668.26 14.9 1669.26 2033.86 ;
        RECT  1618.26 14.9 1619.26 2033.86 ;
        RECT  1568.26 1680.05 1569.26 2033.86 ;
        RECT  1568.26 1430.12 1569.26 1439.32 ;
        RECT  1568.26 1080.05 1569.26 1189.39 ;
        RECT  1568.26 830.12 1569.26 839.38 ;
        RECT  1568.26 480.05 1569.26 589.39 ;
        RECT  1568.26 14.9 1569.26 239.32 ;
        RECT  1518.26 1679.81 1519.26 2033.86 ;
        RECT  1518.26 1429.88 1519.26 1439.56 ;
        RECT  1518.26 1079.81 1519.26 1189.63 ;
        RECT  1518.26 829.88 1519.26 839.56 ;
        RECT  1518.26 479.81 1519.26 589.69 ;
        RECT  1518.26 14.9 1519.26 239.56 ;
        RECT  1468.26 1680.05 1469.26 2033.86 ;
        RECT  1468.26 1430.12 1469.26 1439.32 ;
        RECT  1468.26 1080.05 1469.26 1189.39 ;
        RECT  1468.26 830.12 1469.26 839.38 ;
        RECT  1468.26 480.05 1469.26 589.39 ;
        RECT  1468.26 14.9 1469.26 239.32 ;
        RECT  1418.26 1680.05 1419.26 2033.86 ;
        RECT  1418.26 1430.12 1419.26 1439.32 ;
        RECT  1418.26 1080.05 1419.26 1189.39 ;
        RECT  1418.26 830.12 1419.26 839.38 ;
        RECT  1418.26 480.05 1419.26 589.39 ;
        RECT  1418.26 14.9 1419.26 239.32 ;
        RECT  1368.26 1679.81 1369.26 2033.86 ;
        RECT  1368.26 1429.88 1369.26 1439.56 ;
        RECT  1368.26 1079.81 1369.26 1189.63 ;
        RECT  1368.26 829.88 1369.26 839.56 ;
        RECT  1368.26 479.81 1369.26 589.69 ;
        RECT  1368.26 14.9 1369.26 239.56 ;
        RECT  1318.26 1680.05 1319.26 2033.86 ;
        RECT  1318.26 1430.12 1319.26 1439.32 ;
        RECT  1318.26 1080.05 1319.26 1189.39 ;
        RECT  1318.26 830.12 1319.26 839.38 ;
        RECT  1318.26 480.05 1319.26 589.39 ;
        RECT  1318.26 14.9 1319.26 239.32 ;
        RECT  1268.26 1680.05 1269.26 2033.86 ;
        RECT  1268.26 1430.12 1269.26 1439.32 ;
        RECT  1268.26 1080.05 1269.26 1189.39 ;
        RECT  1268.26 830.12 1269.26 839.38 ;
        RECT  1268.26 480.05 1269.26 589.39 ;
        RECT  1268.26 14.9 1269.26 239.32 ;
        RECT  1218.26 1680.05 1219.26 2033.86 ;
        RECT  1218.26 1430.12 1219.26 1439.32 ;
        RECT  1218.26 1080.05 1219.26 1189.39 ;
        RECT  1218.26 830.12 1219.26 839.38 ;
        RECT  1218.26 480.05 1219.26 589.39 ;
        RECT  1218.26 14.9 1219.26 239.32 ;
        RECT  1168.26 1679.81 1169.26 2033.86 ;
        RECT  1168.26 1429.88 1169.26 1439.56 ;
        RECT  1168.26 1079.81 1169.26 1189.63 ;
        RECT  1168.26 829.88 1169.26 839.56 ;
        RECT  1168.26 479.81 1169.26 589.69 ;
        RECT  1168.26 14.9 1169.26 239.56 ;
        RECT  1118.26 1680.05 1119.26 2033.86 ;
        RECT  1118.26 1430.12 1119.26 1439.32 ;
        RECT  1118.26 1080.05 1119.26 1189.39 ;
        RECT  1118.26 830.12 1119.26 839.38 ;
        RECT  1118.26 480.05 1119.26 589.39 ;
        RECT  1118.26 14.9 1119.26 239.32 ;
        RECT  1068.26 1680.05 1069.26 2033.86 ;
        RECT  1068.26 1430.12 1069.26 1439.32 ;
        RECT  1068.26 1080.05 1069.26 1189.39 ;
        RECT  1068.26 830.12 1069.26 839.38 ;
        RECT  1068.26 480.05 1069.26 589.39 ;
        RECT  1068.26 14.9 1069.26 239.32 ;
        RECT  1018.26 1679.81 1019.26 2033.86 ;
        RECT  1018.26 1429.88 1019.26 1439.56 ;
        RECT  1018.26 1079.81 1019.26 1189.63 ;
        RECT  1018.26 829.88 1019.26 839.56 ;
        RECT  1018.26 479.81 1019.26 589.69 ;
        RECT  1018.26 14.9 1019.26 239.56 ;
        RECT  968.26 1680.05 969.26 2033.86 ;
        RECT  968.26 1430.12 969.26 1439.32 ;
        RECT  968.26 1080.05 969.26 1189.39 ;
        RECT  968.26 830.12 969.26 839.38 ;
        RECT  968.26 480.05 969.26 589.39 ;
        RECT  968.26 14.9 969.26 239.32 ;
        RECT  918.26 1680.05 919.26 2033.86 ;
        RECT  918.26 1430.12 919.26 1439.32 ;
        RECT  918.26 1080.05 919.26 1189.39 ;
        RECT  918.26 830.12 919.26 839.38 ;
        RECT  918.26 480.05 919.26 589.39 ;
        RECT  918.26 14.9 919.26 239.32 ;
        RECT  868.26 14.9 869.26 2033.86 ;
        RECT  818.26 14.9 819.26 2033.86 ;
        RECT  768.26 14.9 769.26 2033.86 ;
        RECT  718.26 2030.12 719.26 2033.86 ;
        RECT  718.26 1680.05 719.26 1789.39 ;
        RECT  718.26 1430.12 719.26 1439.32 ;
        RECT  718.26 1080.05 719.26 1189.39 ;
        RECT  718.26 830.12 719.26 839.38 ;
        RECT  718.26 480.05 719.26 589.39 ;
        RECT  718.26 14.9 719.26 239.32 ;
        RECT  668.26 2029.88 669.26 2033.86 ;
        RECT  668.26 1679.81 669.26 1789.63 ;
        RECT  668.26 1429.88 669.26 1439.56 ;
        RECT  668.26 1079.81 669.26 1189.63 ;
        RECT  668.26 829.88 669.26 839.56 ;
        RECT  668.26 479.81 669.26 589.69 ;
        RECT  668.26 14.9 669.26 239.56 ;
        RECT  618.26 2030.12 619.26 2033.86 ;
        RECT  618.26 1680.05 619.26 1789.39 ;
        RECT  618.26 1430.12 619.26 1439.32 ;
        RECT  618.26 1080.05 619.26 1189.39 ;
        RECT  618.26 830.12 619.26 839.38 ;
        RECT  618.26 480.05 619.26 589.39 ;
        RECT  618.26 14.9 619.26 239.32 ;
        RECT  568.26 2030.12 569.26 2033.86 ;
        RECT  568.26 1680.05 569.26 1789.39 ;
        RECT  568.26 1430.12 569.26 1439.32 ;
        RECT  568.26 1080.05 569.26 1189.39 ;
        RECT  568.26 830.12 569.26 839.38 ;
        RECT  568.26 480.05 569.26 589.39 ;
        RECT  568.26 14.9 569.26 239.32 ;
        RECT  518.26 2029.88 519.26 2033.86 ;
        RECT  518.26 1679.81 519.26 1789.63 ;
        RECT  518.26 1429.88 519.26 1439.56 ;
        RECT  518.26 1079.81 519.26 1189.63 ;
        RECT  518.26 829.88 519.26 839.56 ;
        RECT  518.26 479.81 519.26 589.69 ;
        RECT  518.26 14.9 519.26 239.56 ;
        RECT  468.26 2030.12 469.26 2033.86 ;
        RECT  468.26 1680.05 469.26 1789.39 ;
        RECT  468.26 1430.12 469.26 1439.32 ;
        RECT  468.26 1080.05 469.26 1189.39 ;
        RECT  468.26 830.12 469.26 839.38 ;
        RECT  468.26 480.05 469.26 589.39 ;
        RECT  468.26 14.9 469.26 239.32 ;
        RECT  418.26 2030.12 419.26 2033.86 ;
        RECT  418.26 1680.05 419.26 1789.39 ;
        RECT  418.26 1430.12 419.26 1439.32 ;
        RECT  418.26 1080.05 419.26 1189.39 ;
        RECT  418.26 830.12 419.26 839.38 ;
        RECT  418.26 480.05 419.26 589.39 ;
        RECT  418.26 14.9 419.26 239.32 ;
        RECT  368.26 2030.12 369.26 2033.86 ;
        RECT  368.26 1680.05 369.26 1789.39 ;
        RECT  368.26 1430.12 369.26 1439.32 ;
        RECT  368.26 1080.05 369.26 1189.39 ;
        RECT  368.26 830.12 369.26 839.38 ;
        RECT  368.26 480.05 369.26 589.39 ;
        RECT  368.26 14.9 369.26 239.32 ;
        RECT  318.26 2029.88 319.26 2033.86 ;
        RECT  318.26 1679.81 319.26 1789.63 ;
        RECT  318.26 1429.88 319.26 1439.56 ;
        RECT  318.26 1079.81 319.26 1189.63 ;
        RECT  318.26 829.88 319.26 839.56 ;
        RECT  318.26 479.81 319.26 589.69 ;
        RECT  318.26 14.9 319.26 239.56 ;
        RECT  268.26 2030.12 269.26 2033.86 ;
        RECT  268.26 1680.05 269.26 1789.39 ;
        RECT  268.26 1430.12 269.26 1439.32 ;
        RECT  268.26 1080.05 269.26 1189.39 ;
        RECT  268.26 830.12 269.26 839.38 ;
        RECT  268.26 480.05 269.26 589.39 ;
        RECT  268.26 14.9 269.26 239.32 ;
        RECT  218.26 2030.12 219.26 2033.86 ;
        RECT  218.26 1680.05 219.26 1789.39 ;
        RECT  218.26 1430.12 219.26 1439.32 ;
        RECT  218.26 1080.05 219.26 1189.39 ;
        RECT  218.26 830.12 219.26 839.38 ;
        RECT  218.26 480.05 219.26 589.39 ;
        RECT  218.26 14.9 219.26 239.32 ;
        RECT  168.26 2029.88 169.26 2033.86 ;
        RECT  168.26 1679.81 169.26 1789.63 ;
        RECT  168.26 1429.88 169.26 1439.56 ;
        RECT  168.26 1079.81 169.26 1189.63 ;
        RECT  168.26 829.88 169.26 839.56 ;
        RECT  168.26 479.81 169.26 589.69 ;
        RECT  168.26 14.9 169.26 239.56 ;
        RECT  118.26 2030.12 119.26 2033.86 ;
        RECT  118.26 1680.05 119.26 1789.39 ;
        RECT  118.26 1430.12 119.26 1439.32 ;
        RECT  118.26 1080.05 119.26 1189.39 ;
        RECT  118.26 830.12 119.26 839.38 ;
        RECT  118.26 480.05 119.26 589.39 ;
        RECT  118.26 14.9 119.26 239.32 ;
        RECT  68.26 2030.12 69.26 2033.86 ;
        RECT  68.26 1680.05 69.26 1789.39 ;
        RECT  68.26 1430.12 69.26 1439.32 ;
        RECT  68.26 1080.05 69.26 1189.39 ;
        RECT  68.26 830.12 69.26 839.38 ;
        RECT  68.26 480.05 69.26 589.39 ;
        RECT  68.26 14.9 69.26 239.32 ;
        RECT  18.26 14.9 19.26 2033.86 ;
    END
  END VGND
  OBS
    LAYER Metal1 ;
     RECT  0 0 1800 2050 ;
    LAYER Metal2 ;
     RECT  0 0 1800 2050 ;
    LAYER Metal3 ;
     RECT  0 0 1800 2050 ;
    LAYER Metal4 ;
     RECT  0 0 1800 2050 ;
    LAYER TopMetal1 ;
     RECT  0 0 1800 2050 ;
  END
END ino_fetch
END LIBRARY
